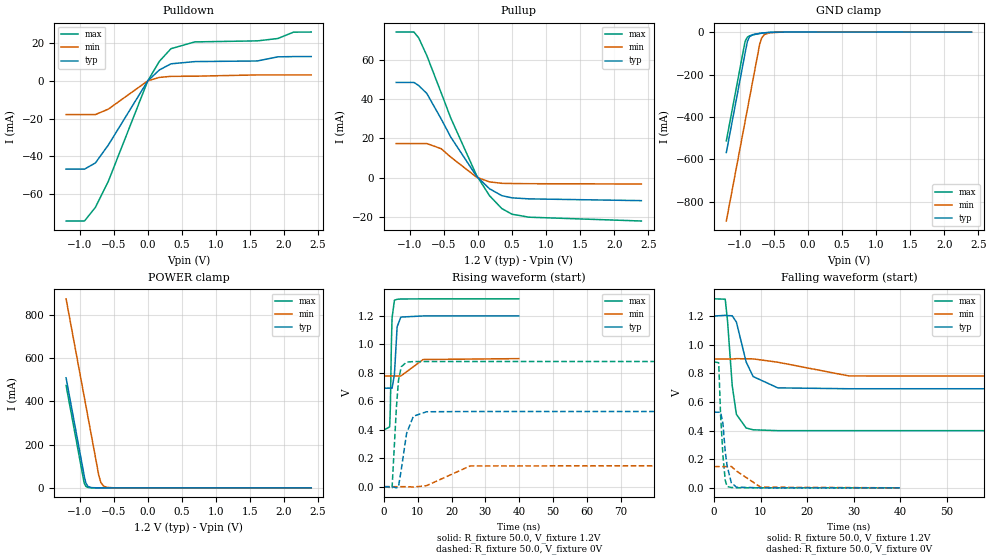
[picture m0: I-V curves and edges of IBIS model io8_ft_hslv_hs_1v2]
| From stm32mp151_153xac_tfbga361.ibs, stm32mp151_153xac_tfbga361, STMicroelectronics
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[Model]   io8_ft_hslv_hs_1v2
Model_type I/O
Polarity   Non-Inverting
Enable   Active-Low
| CAP_THRESHOLD on pad IOFT is "UDTCAPC" :
| Rising=20.00f vddiom   Falling=80.00f vddiom
| C_comp min and max val. don't necessarily correlate with the min and max pvt
| but are the smallest and greatest pad capacitance found.
| var   typ   min   max
C_comp   3.08865pF  3.06550pF  3.10825pF
|C_comp_pullup   1.81640pF  1.58310pF  1.74795pF
|C_comp_pulldown   1.27225pF  1.48240pF  1.36030pF
Vinl = 360.0mV
Vinh = 792.0mV
Vmeas = 600.0mV   | Reference voltage for timing measurements
Cref  = 50.0pF   | Timing specification test load capacitance value
Rref  = 100.0MOhm   | Timing specification test load resistance value
Vref  = 0V   | Timing specification test load voltage
[Model Spec]
| TIME_THRESHOLD on pin ZIV11 is "CMOS" :
| Rising=40.00f vdd   Falling=60.00f vdd
Vinl 463.60000mV 362.60000mV 506.60000mV
Vinh 741.40000mV 545.40000mV 817.40000mV
| variable   typ   min   max
[Temperature Range] 25.0 140.0 -40.0
| variable   typ   min   max
[Voltage Range] 1.2V 900.0mV 1.32V
| variable   typ   min   max
[POWER Clamp Reference] 1.2V 900.0mV 1.32V
| variable   typ   min   max
[GND Clamp Reference] 0V 0V 0V
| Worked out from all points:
|   slope of the pulldown table from 0 to 0.18 V, typ, clamps not added: 30 ohm
|   slope of the pullup table from 0 to 0.18 V, typ, clamps not added: 31.1 ohm
|   GND clamp passes 1 mA (typ) near -0.52 V on its own axis
|   POWER clamp passes 1 mA (typ) near -0.83 V on its own axis
|   rising waveform, R_fixture 50.0, V_fixture 1.2V: 20-80 % time 689ps typ, 1.81ns min, 414ps max; typ from 0.692 V to 1.2 V
|   falling waveform, R_fixture 50.0, V_fixture 1.2V: 20-80 % time 2.79ns typ, 6.92ns min, 1.4ns max; typ from 1.2 V to 0.692 V
|   rising waveform, R_fixture 50.0, V_fixture 0V: 20-80 % time 2.16ns typ, 4.94ns min, 1.21ns max; typ from 0 V to 0.528 V
|   falling waveform, R_fixture 50.0, V_fixture 0V: 20-80 % time 1.12ns typ, 2.39ns min, 840ps max; typ from 0.528 V to 0 V
[POWER Clamp]
-1.2V     508.8mA    874.1mA    473.5mA
-940mV    66.83mA    432.1mA    31.5mA
-930mV    49.83mA    415.1mA    19.15mA
-910mV    22.88mA    381.1mA    7.077mA
-880mV    7.117mA    330.1mA    1.59mA
-830mV    1.017mA    245.1mA    132uA
-720mV    14.05uA    58.12mA    554nA
-690mV    4.373uA    25.03mA    124.7nA
-650mV    922.4nA    8.136mA    17.22nA
-600mV    132.5nA    1.998mA    1.555nA
-490mV    2.736nA    90.9uA     103pA
2.4V      0A         0A         0A
[GND Clamp]
-1.2V     -567.2mA   -889.7mA   -512.2mA
-930mV    -108.2mA   -430.7mA   -53.23mA
-920mV    -91.21mA   -413.7mA   -40.49mA
-890mV    -43.51mA   -362.7mA   -23.59mA
-860mV    -22.57mA   -311.7mA   -17.89mA
-810mV    -12.11mA   -226.7mA   -13.23mA
-710mV    -6.053mA   -57.05mA   -7.064mA
-680mV    -4.908mA   -27.37mA   -5.632mA
-640mV    -3.605mA   -11.51mA   -3.985mA
-560mV    -1.665mA   -3.218mA   -1.61mA
-360mV    -34.72uA   -209.4uA   -9.248uA
2.4V      3.381nA    1.198uA    162.5pA
| variable   typ   min   max
[Pullup Reference] 1.2V 900.0mV 1.32V
| variable   typ   min   max
[Pulldown Reference] 0V 0V 0V
[Pullup]
-1.2V     48.48mA    17.42mA    74.09mA
-940mV    48.48mA    17.42mA    74.09mA
-870mV    46.92mA    17.42mA    71.14mA
-750mV    42.85mA    17.42mA    62.1mA
-540mV    29.95mA    14.82mA    43.25mA
-400mV    20.78mA    10.58mA    30.49mA
-20mV     787.9uA    340.3uA    1.238mA
170mV     -5.53mA    -2.053mA   -9.057mA
350mV     -9.029mA   -2.778mA   -15.58mA
500mV     -10.16mA   -2.879mA   -18.47mA
750mV     -10.68mA   -2.969mA   -19.99mA
2.4V      -11.58mA   -3.134mA   -21.93mA
[Pulldown]
-1.2V     -46.7mA    -17.86mA   -74.13mA
-930mV    -46.7mA    -17.86mA   -74.13mA
-770mV    -43.45mA   -17.86mA   -66.94mA
-580mV    -33.98mA   -14.99mA   -53.18mA
0V        0A         -3pA       0A
170mV     5.742mA    1.792mA    10.3mA
340mV     8.972mA    2.348mA    16.97mA
690mV     10.15mA    2.431mA    20.56mA
1.61V     10.49mA    3.108mA    21.11mA
1.91V     12.66mA    3.108mA    22.36mA
2.14V     12.8mA     3.108mA    25.73mA
2.4V      12.8mA     3.108mA    25.78mA
[Ramp]
dV/dt_r 316.99739mV/2.16461ns 89.08709mV/4.9382ns 527.83784mV/1.2101ns
dV/dt_f 304.66521mV/2.79208ns 73.18473mV/6.92283ns 552.41172mV/1.39788ns
R_load = 50.0
| Removed startup time: 0s 0s 0s  .
| Removed end time: 39.9ns.
[Rising Waveform]
R_fixture   = 50.0
V_fixture   = 1.2V
V_fixture_min = 900.0mV
V_fixture_max = 1.32V
0s        692.2mV    778mV      399.3mV
1.7ns     692.6mV    778.1mV    420.1mV
1.9ns     692.6mV    778.1mV    559.3mV
2.2ns     692.3mV    778.1mV    1.003V
2.4ns     691.3mV    778.1mV    1.187V
3.1ns     788mV      778.1mV    1.31V
3.9ns     1.124V     778.1mV    1.317V
5ns       1.192V     778.1mV    1.319V
11.6ns    1.2V       893.8mV    1.32V
39.9ns    1.2V       900mV      1.32V
| Removed startup time: 0s 0s 0s  .
| Removed end time: 199.9ns.
[Falling Waveform]
R_fixture   = 50.0
V_fixture   = 1.2V
V_fixture_min = 900.0mV
V_fixture_max = 1.32V
0s        1.2V       900mV      1.32V
2.4ns     1.205V     900mV      1.318V
2.9ns     1.203V     900mV      1.164V
3.9ns     1.202V     899.9mV    714.9mV
4.8ns     1.158V     902.4mV    513.4mV
6.9ns     879.3mV    901.1mV    418mV
8.4ns     777.4mV    900.7mV    405.5mV
13.7ns    698.4mV    877.6mV    399.5mV
29ns      692.2mV    781.7mV    399.3mV
199.9ns   692.2mV    778mV      399.3mV
| Removed startup time: 0s 0s 0s  .
| Removed end time: 199.9ns.
[Rising Waveform]
R_fixture   = 50.0
V_fixture   = 0V
V_fixture_min = 0V
V_fixture_max = 0V
0s        -49.46nV   697.7nV    -2.584uV
2.4ns     60.41uV    53.31nV    -8.2mV
3.7ns     -8.111mV   -3.227uV   562.6mV
4.3ns     193.3uV    -1.133uV   745.8mV
5.1ns     115.8mV    1.14uV     842mV
6.7ns     374.3mV    -107.7uV   875.7mV
8.7ns     495.1mV    -2.465mV   879.1mV
12.6ns    526.6mV    7.06mV     879.6mV
25.5ns    528.2mV    145.8mV    879.7mV
199.9ns   528.3mV    148.5mV    879.7mV
| Removed startup time: 0s 0s 0s  .
| Removed end time: 39.9ns.
[Falling Waveform]
R_fixture   = 50.0
V_fixture   = 0V
V_fixture_min = 0V
V_fixture_max = 0V
0s        528.3mV    148.5mV    879.7mV
1ns       528.4mV    148.5mV    873.7mV
1.4ns     529.1mV    148.5mV    508mV
1.9ns     450.6mV    148.5mV    228.6mV
2.4ns     253.3mV    148.5mV    53.1mV
2.8ns     153.9mV    148.5mV    9.578mV
3.7ns     36.42mV    149.8mV    2.479mV
4.8ns     4.812mV    117.7mV    920.1uV
10ns      258.6uV    4.938mV    32.97uV
39.9ns    34.97nV    3.183uV    29.06nV
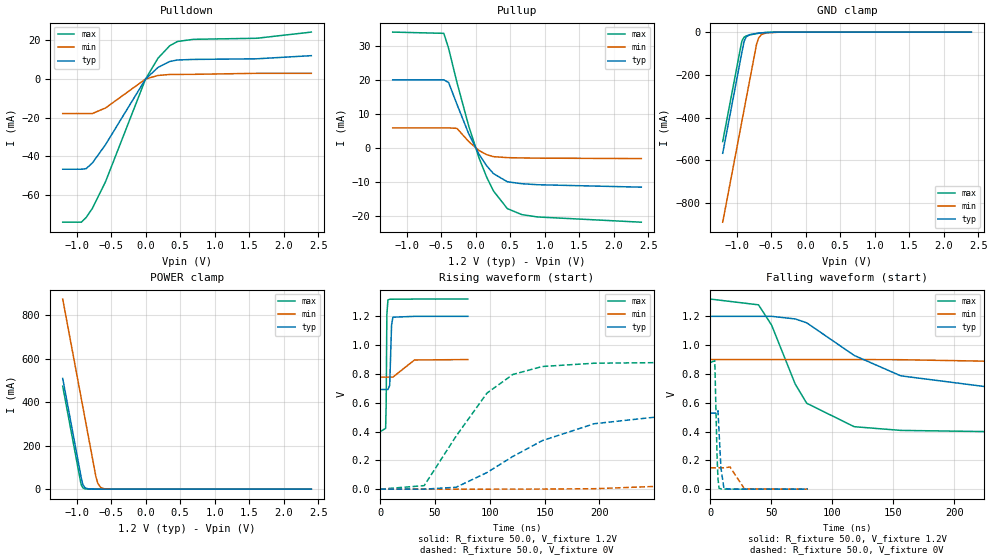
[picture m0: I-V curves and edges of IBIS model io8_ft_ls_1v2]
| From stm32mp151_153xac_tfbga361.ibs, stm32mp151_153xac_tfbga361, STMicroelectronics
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[Model]   io8_ft_ls_1v2
Model_type I/O
Polarity   Non-Inverting
Enable   Active-Low
| CAP_THRESHOLD on pad IOFT is "UDTCAPC" :
| Rising=20.00f vddiom   Falling=80.00f vddiom
| C_comp min and max val. don't necessarily correlate with the min and max pvt
| but are the smallest and greatest pad capacitance found.
| var   typ   min   max
C_comp   3.10955pF  3.08200pF  3.12755pF
|C_comp_pullup   1.83575pF  1.59880pF  1.76540pF
|C_comp_pulldown   1.27380pF  1.48320pF  1.36215pF
Vinl = 360.0mV
Vinh = 792.0mV
Vmeas = 600.0mV   | Reference voltage for timing measurements
Cref  = 50.0pF   | Timing specification test load capacitance value
Rref  = 100.0MOhm   | Timing specification test load resistance value
Vref  = 0V   | Timing specification test load voltage
[Model Spec]
| TIME_THRESHOLD on pin ZIV11 is "CMOS" :
| Rising=40.00f vdd   Falling=60.00f vdd
Vinl 463.60000mV 362.60000mV 506.60000mV
Vinh 741.40000mV 545.40000mV 817.40000mV
| variable   typ   min   max
[Temperature Range] 25.0 140.0 -40.0
| variable   typ   min   max
[Voltage Range] 1.2V 900.0mV 1.32V
| variable   typ   min   max
[POWER Clamp Reference] 1.2V 900.0mV 1.32V
| variable   typ   min   max
[GND Clamp Reference] 0V 0V 0V
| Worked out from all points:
|   slope of the pulldown table from 0 to 0.18 V, typ, clamps not added: 30 ohm
|   slope of the pullup table from 0 to 0.18 V, typ, clamps not added: 31.1 ohm
|   GND clamp passes 1 mA (typ) near -0.52 V on its own axis
|   POWER clamp passes 1 mA (typ) near -0.83 V on its own axis
|   rising waveform, R_fixture 50.0, V_fixture 1.2V: 20-80 % time 987ps typ, 2.96ns min, 508ps max; typ from 0.692 V to 1.2 V
|   falling waveform, R_fixture 50.0, V_fixture 1.2V: 20-80 % time 62.7ns typ, 177ns min, 29.8ns max; typ from 1.2 V to 0.692 V
|   rising waveform, R_fixture 50.0, V_fixture 0V: 20-80 % time 82.5ns typ, 195ns min, 47.7ns max; typ from 0 V to 0.528 V
|   falling waveform, R_fixture 50.0, V_fixture 0V: 20-80 % time 2.14ns typ, 4.88ns min, 1.52ns max; typ from 0.528 V to 0 V
[POWER Clamp]
-1.2V     508.8mA    874.1mA    473.5mA
-940mV    66.83mA    432.1mA    31.5mA
-930mV    49.83mA    415.1mA    19.15mA
-910mV    22.88mA    381.1mA    7.077mA
-880mV    7.117mA    330.1mA    1.59mA
-830mV    1.017mA    245.1mA    132uA
-720mV    14.05uA    58.12mA    554nA
-690mV    4.373uA    25.03mA    124.7nA
-650mV    922.4nA    8.136mA    17.22nA
-600mV    132.5nA    1.998mA    1.555nA
-490mV    2.763nA    90.9uA     103.5pA
2.4V      0A         0A         0A
[GND Clamp]
-1.2V     -567.2mA   -889.7mA   -512.2mA
-930mV    -108.2mA   -430.7mA   -53.23mA
-920mV    -91.21mA   -413.7mA   -40.49mA
-890mV    -43.51mA   -362.7mA   -23.59mA
-860mV    -22.57mA   -311.7mA   -17.89mA
-810mV    -12.11mA   -226.7mA   -13.23mA
-710mV    -6.053mA   -57.05mA   -7.064mA
-680mV    -4.908mA   -27.37mA   -5.632mA
-640mV    -3.605mA   -11.51mA   -3.985mA
-560mV    -1.665mA   -3.218mA   -1.61mA
-360mV    -34.72uA   -209.4uA   -9.248uA
2.4V      3.381nA    1.198uA    162.5pA
| variable   typ   min   max
[Pullup Reference] 1.2V 900.0mV 1.32V
| variable   typ   min   max
[Pulldown Reference] 0V 0V 0V
[Pullup]
-1.2V     20.14mA    5.941mA    34.24mA
-460mV    20.14mA    5.941mA    33.87mA
-390mV    19.31mA    5.941mA    29.39mA
-270mV    12.92mA    5.787mA    19.38mA
-100mV    4.22mA     1.911mA    6.527mA
50mV      -1.845mA   -758.1uA   -2.941mA
160mV     -5.263mA   -1.972mA   -8.6mA
260mV     -7.588mA   -2.569mA   -12.73mA
460mV     -9.985mA   -2.858mA   -17.92mA
670mV     -10.56mA   -2.944mA   -19.69mA
900mV     -10.86mA   -3.007mA   -20.39mA
2.4V      -11.58mA   -3.134mA   -21.93mA
[Pulldown]
-1.2V     -46.7mA    -17.86mA   -74.13mA
-930mV    -46.7mA    -17.86mA   -74.13mA
-860mV    -46.38mA   -17.86mA   -71.67mA
-770mV    -43.45mA   -17.86mA   -66.94mA
-580mV    -33.98mA   -14.99mA   -53.18mA
0V        0A         0A         0A
180mV     6.001mA    1.854mA    10.79mA
350mV     9.086mA    2.357mA    17.24mA
460mV     9.857mA    2.399mA    19.42mA
690mV     10.15mA    2.431mA    20.56mA
1.61V     10.48mA    2.965mA    21.11mA
2.4V      12.11mA    2.965mA    24.31mA
[Ramp]
dV/dt_r 316.97841mV/82.49598ns 88.45552mV/195.47658ns 527.82343mV/47.69496ns
dV/dt_f 304.65738mV/62.70339ns 72.73727mV/175.08762ns 552.41102mV/29.81872ns
R_load = 50.0
| Removed startup time: 0s 0s 0s  .
| Removed end time: 79.9ns.
[Rising Waveform]
R_fixture   = 50.0
V_fixture   = 1.2V
V_fixture_min = 900.0mV
V_fixture_max = 1.32V
0s        692.2mV    778mV      399.3mV
4.9ns     692.2mV    778mV      422.3mV
5.4ns     692.2mV    778mV      597.9mV
6ns       692.3mV    778mV      1.212V
7ns       691.6mV    778mV      1.314V
8.6ns     720.2mV    778mV      1.319V
10.3ns    1.14V      778mV      1.319V
11.5ns    1.194V     778mV      1.319V
31.2ns    1.2V       896.9mV    1.32V
79.9ns    1.2V       899.9mV    1.32V
| Removed startup time: 0s 0s 0s  .
| Removed end time: 799.9ns.
[Falling Waveform]
R_fixture   = 50.0
V_fixture   = 1.2V
V_fixture_min = 900.0mV
V_fixture_max = 1.32V
0s        1.2V       900mV      1.32V
39.5ns    1.2V       900.1mV    1.28V
50.3ns    1.2V       900mV      1.138V
69.6ns    1.182V     900mV      729.4mV
79ns      1.155V     900mV      596.4mV
117.9ns   928.6mV    900mV      433.8mV
156ns     787mV      898.9mV    408.1mV
224.4ns   713mV      888.9mV    400mV
444.4ns   692.4mV    800.4mV    399.3mV
799.9ns   692.2mV    778.8mV    399.3mV
| Removed startup time: 0s 0s 0s  .
| Removed end time: 799.9ns.
[Rising Waveform]
R_fixture   = 50.0
V_fixture   = 0V
V_fixture_min = 0V
V_fixture_max = 0V
0s        50.56nV    1.017uV    137.1nV
40.1ns    -72.19uV   -26.3uV    24.69mV
69.3ns    13.35mV    -3.105uV   369.2mV
97.4ns    115.4mV    34.09uV    667.1mV
121ns     227.2mV    177.3uV    796.4mV
147.9ns   337.1mV    642.8uV    851.7mV
195.3ns   454.4mV    3.028mV    874.5mV
265.7ns   512.1mV    23.15mV    879.4mV
490ns     528.1mV    122.7mV    879.7mV
799.9ns   528.3mV    147.4mV    879.7mV
| Removed startup time: 0s 0s 0s  .
| Removed end time: 79.9ns.
[Falling Waveform]
R_fixture   = 50.0
V_fixture   = 0V
V_fixture_min = 0V
V_fixture_max = 0V
0s        528.3mV    148.5mV    879.7mV
3.7ns     528.3mV    148.5mV    890.9mV
5.5ns     529.1mV    148.5mV    245.2mV
6.3ns     544.5mV    148.5mV    72.91mV
7.2ns     396.6mV    148.5mV    6.735mV
8.7ns     149.3mV    148.5mV    1.774mV
11.2ns    5.194mV    148.5mV    520.6uV
16.2ns    350.8uV    153.7mV    289.9uV
28ns      125.5uV    1.631mV    273.3uV
79.9ns    139.6uV    28.79uV    55.94uV
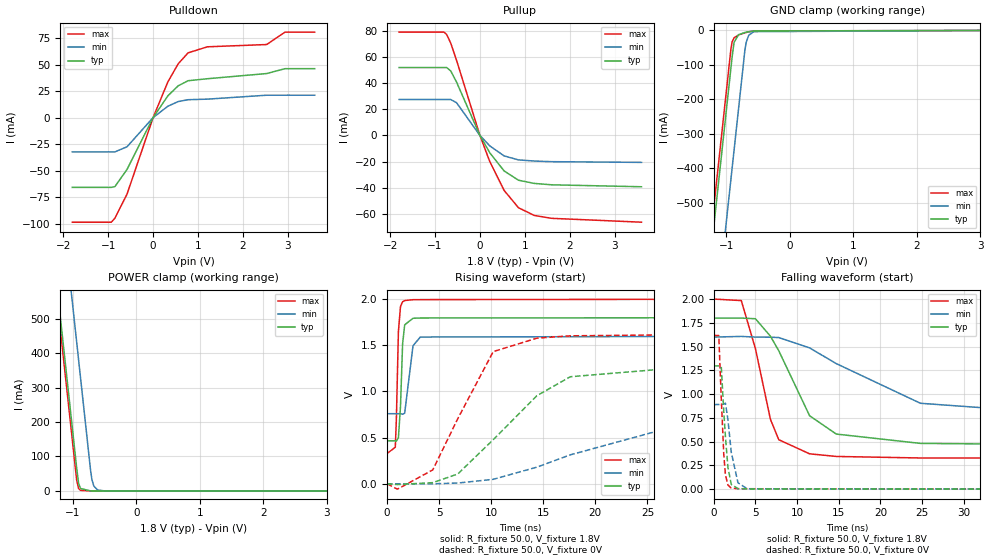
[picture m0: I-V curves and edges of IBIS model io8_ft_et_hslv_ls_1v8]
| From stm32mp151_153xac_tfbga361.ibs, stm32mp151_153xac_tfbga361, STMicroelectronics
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[Model]   io8_ft_et_hslv_ls_1v8
Model_type I/O
Polarity   Non-Inverting
Enable   Active-Low
| CAP_THRESHOLD on pad IOFT is "UDTCAPC" :
| Rising=20.00f vddiom   Falling=80.00f vddiom
| C_comp min and max val. don't necessarily correlate with the min and max pvt
| but are the smallest and greatest pad capacitance found.
| var   typ   min   max
C_comp   3.43098pF  3.42356pF  3.49920pF
|C_comp_pullup   1.96775pF  2.05990pF  1.91900pF
|C_comp_pulldown   1.46323pF  1.36366pF  1.58020pF
Vinl = 640.0mV
Vinh = 1.2V
Vmeas = 900.0mV   | Reference voltage for timing measurements
Cref  = 50.0pF   | Timing specification test load capacitance value
Rref  = 100.0MOhm   | Timing specification test load resistance value
Vref  = 0V   | Timing specification test load voltage
[Model Spec]
| TIME_THRESHOLD on pin ZIV11 is "CMOS" :
| Rising=40.00f vdd   Falling=60.00f vdd
Vinl 738.60000mV 665.60000mV 824.60000mV
Vinh 1.04640V 924.40000mV 1.13940V
| variable   typ   min   max
[Temperature Range] 25.0 140.0 -40.0
| variable   typ   min   max
[Voltage Range] 1.8V 1.6V 2.0V
| variable   typ   min   max
[POWER Clamp Reference] 1.8V 1.6V 2.0V
| variable   typ   min   max
[GND Clamp Reference] 0V 0V 0V
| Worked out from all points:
|   slope of the pulldown table from 0 to 0.27 V, typ, clamps not added: 16 ohm
|   slope of the pullup table from 0 to 0.27 V, typ, clamps not added: 17 ohm
|   GND clamp passes 1 mA (typ) near -0.52 V on its own axis
|   POWER clamp passes 1 mA (typ) near -0.83 V on its own axis
|   rising waveform, R_fixture 50.0, V_fixture 1.8V: 20-80 % time 258ps typ, 399ps min, 218ps max; typ from 0.466 V to 1.8 V
|   falling waveform, R_fixture 50.0, V_fixture 1.8V: 20-80 % time 4.53ns typ, 10.9ns min, 2.52ns max; typ from 1.8 V to 0.466 V
|   rising waveform, R_fixture 50.0, V_fixture 0V: 20-80 % time 7ns typ, 15.5ns min, 3.89ns max; typ from 0 V to 1.3 V
|   falling waveform, R_fixture 50.0, V_fixture 0V: 20-80 % time 589ps typ, 785ps min, 467ps max; typ from 1.3 V to 0 V
[POWER Clamp]
-1.8V     1.529A     1.894A     1.494A
-940mV    66.83mA    432.1mA    31.5mA
-910mV    22.88mA    381.1mA    7.077mA
-880mV    7.117mA    330.1mA    1.59mA
-720mV    14.05uA    58.12mA    554nA
-700mV    6.453uA    33.14mA    205nA
-670mV    2.008uA    14.27mA    46.29nA
-610mV    195.5nA    2.645mA    2.508nA
-500mV    3.96nA     120.4uA    139.7pA
3.6V      0A         0A         0A
[GND Clamp]
-1.8V     -1.588A    -1.91A     -1.533A
-1.26V    -670.3mA   -992.4mA   -614.9mA
-1.2V     -568.3mA   -890.4mA   -512.9mA
-930mV    -109.3mA   -431.4mA   -53.86mA
-910mV    -75.33mA   -397.4mA   -32.91mA
-880mV    -34.88mA   -346.4mA   -21.56mA
-810mV    -12.56mA   -227.4mA   -13.55mA
-710mV    -6.275mA   -57.63mA   -7.234mA
-690mV    -5.461mA   -35.21mA   -6.234mA
-650mV    -4.039mA   -14.43mA   -4.463mA
-570mV    -1.908mA   -3.832mA   -1.869mA
3.6V      5.084nA    1.599uA    245.6pA
| variable   typ   min   max
[Pullup Reference] 1.8V 1.6V 2.0V
| variable   typ   min   max
[Pulldown Reference] 0V 0V 0V
[Pullup]
-1.8V     51.8mA     27.39mA    78.89mA
-800mV    51.8mA     27.39mA    78.89mA
-740mV    51.8mA     27.39mA    77.04mA
-650mV    49.26mA    27.39mA    70.49mA
-520mV    40.7mA     24.96mA    57.36mA
0V        7.41pA     1.331nA    4.294pA
220mV     -13.28mA   -8.01mA    -19.99mA
540mV     -27.17mA   -15.69mA   -42.05mA
860mV     -34.25mA   -18.73mA   -55.26mA
1.21V     -36.68mA   -19.6mA    -61.13mA
1.6V      -37.75mA   -20.08mA   -63.35mA
3.6V      -39.24mA   -20.62mA   -66.3mA
[Pulldown]
-1.8V     -65.8mA    -32.31mA   -98.64mA
-930mV    -65.8mA    -32.31mA   -98.64mA
-850mV    -65.04mA   -32.31mA   -94.81mA
-580mV    -48.83mA   -27.49mA   -72.14mA
0V        0A         -3pA       0A
330mV     20.59mA    10.79mA    33.74mA
560mV     30.02mA    15.15mA    50.81mA
780mV     34.81mA    16.9mA     61.1mA
1.21V     36.69mA    17.44mA    66.81mA
2.53V     41.58mA    21.14mA    68.95mA
2.94V     46.18mA    21.14mA    80.69mA
3.6V      46.18mA    21.14mA    80.69mA
[Ramp]
dV/dt_r 777.92781mV/6.99993ns 534.16918mV/15.51711ns 970.1271mV/3.88692ns
dV/dt_f 800.5972mV/4.5251ns 504.69998mV/10.92983ns 1.00395V/2.5137ns
R_load = 50.0
| Removed startup time: 0s 0s 0s  .
| Removed end time: 49.9ns.
[Rising Waveform]
R_fixture   = 50.0
V_fixture   = 1.8V
V_fixture_min = 1.6V
V_fixture_max = 2.0V
0s        465.7mV    758.8mV    326.7mV
800ps     465.2mV    758.9mV    395.8mV
900ps     461mV      758.9mV    690.1mV
1.1ns     498.4mV    758.8mV    1.65V
1.3ns     838.9mV    759mV      1.92V
1.5ns     1.512V     753.4mV    1.971V
1.7ns     1.721V     764mV      1.984V
2.5ns     1.792V     1.494V     1.993V
3.2ns     1.795V     1.589V     1.994V
49.9ns    1.8V       1.6V       2V
| Removed startup time: 0s 0s 0s  .
| Removed end time: 279.9ns.
[Falling Waveform]
R_fixture   = 50.0
V_fixture   = 1.8V
V_fixture_min = 1.6V
V_fixture_max = 2.0V
0s        1.8V       1.6V       2V
3.3ns     1.8V       1.607V     1.984V
5ns       1.793V     1.6V       1.478V
6.8ns     1.609V     1.599V     734.3mV
7.8ns     1.456V     1.595V     520.3mV
11.5ns    772.4mV    1.486V     371.8mV
14.7ns    579.7mV    1.321V     344.2mV
24.8ns    481.5mV    903.6mV    328.1mV
45.4ns    466.2mV    773.9mV    326.7mV
279.9ns   465.7mV    758.8mV    326.7mV
| Removed startup time: 0s 0s 0s  .
| Removed end time: 279.9ns.
[Rising Waveform]
R_fixture   = 50.0
V_fixture   = 0V
V_fixture_min = 0V
V_fixture_max = 0V
0s        169.1nV    -242nV     -4.867uV
1ns       -8.395mV   -89.61uV   -58.18mV
4.4ns     12.46mV    -261.8uV   150.9mV
6.8ns     106.3mV    8.15mV     705.5mV
10.2ns    477.5mV    48.4mV     1.431V
14.4ns    954.3mV    180.5mV    1.577V
17.6ns    1.159V     313.4mV    1.602V
31.6ns    1.289V     744.2mV    1.617V
50.9ns    1.296V     873.8mV    1.617V
279.9ns   1.297V     890.3mV    1.617V
| Removed startup time: 0s 0s 0s  .
| Removed end time: 49.9ns.
[Falling Waveform]
R_fixture   = 50.0
V_fixture   = 0V
V_fixture_min = 0V
V_fixture_max = 0V
0s        1.297V     890.3mV    1.617V
600ps     1.296V     890.4mV    1.616V
900ps     1.292V     890.6mV    952.5mV
1.2ns     810.4mV    895mV      366.1mV
1.4ns     551.5mV    904.7mV    150.7mV
1.7ns     229.1mV    729.5mV    43.25mV
2.1ns     50.05mV    388.1mV    11.1mV
2.9ns     5.096mV    67.91mV    4.999mV
4ns       2.785mV    4.354mV    4.542mV
49.9ns    4.402uV    16.85uV    7.556uV
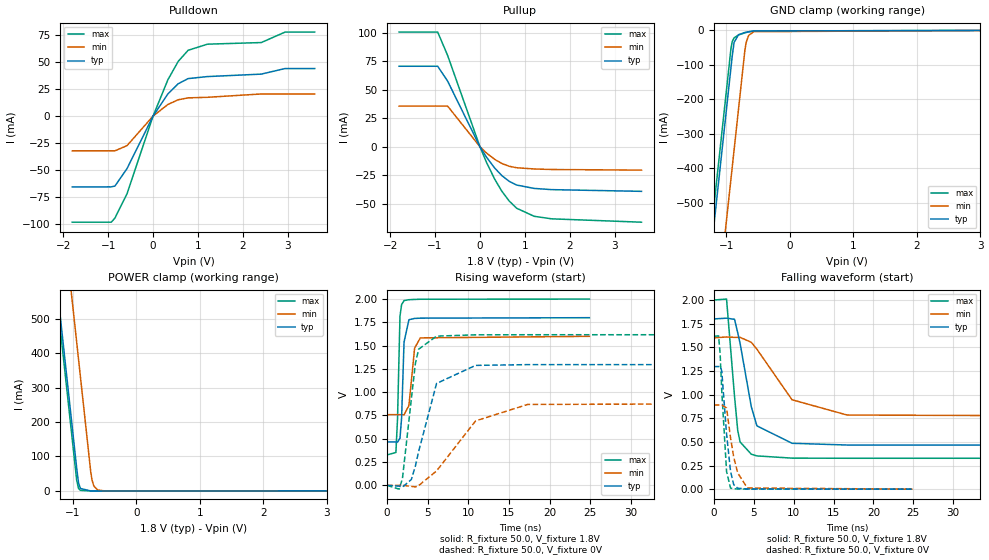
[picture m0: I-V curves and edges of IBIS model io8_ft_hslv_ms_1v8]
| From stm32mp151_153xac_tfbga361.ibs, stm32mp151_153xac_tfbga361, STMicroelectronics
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[Model]   io8_ft_hslv_ms_1v8
Model_type I/O
Polarity   Non-Inverting
Enable   Active-Low
| CAP_THRESHOLD on pad IOFT is "UDTCAPC" :
| Rising=20.00f vddiom   Falling=80.00f vddiom
| C_comp min and max val. don't necessarily correlate with the min and max pvt
| but are the smallest and greatest pad capacitance found.
| var   typ   min   max
C_comp   3.40998pF  3.40231pF  3.47825pF
|C_comp_pullup   1.96225pF  2.05415pF  1.91340pF
|C_comp_pulldown   1.44773pF  1.34816pF  1.56485pF
Vinl = 640.0mV
Vinh = 1.2V
Vmeas = 900.0mV   | Reference voltage for timing measurements
Cref  = 50.0pF   | Timing specification test load capacitance value
Rref  = 100.0MOhm   | Timing specification test load resistance value
Vref  = 0V   | Timing specification test load voltage
[Model Spec]
| TIME_THRESHOLD on pin ZIV11 is "CMOS" :
| Rising=40.00f vdd   Falling=60.00f vdd
Vinl 738.60000mV 665.60000mV 824.60000mV
Vinh 1.04640V 924.40000mV 1.13940V
| variable   typ   min   max
[Temperature Range] 25.0 140.0 -40.0
| variable   typ   min   max
[Voltage Range] 1.8V 1.6V 2.0V
| variable   typ   min   max
[POWER Clamp Reference] 1.8V 1.6V 2.0V
| variable   typ   min   max
[GND Clamp Reference] 0V 0V 0V
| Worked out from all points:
|   slope of the pulldown table from 0 to 0.27 V, typ, clamps not added: 16 ohm
|   slope of the pullup table from 0 to 0.27 V, typ, clamps not added: 17 ohm
|   GND clamp passes 1 mA (typ) near -0.52 V on its own axis
|   POWER clamp passes 1 mA (typ) near -0.83 V on its own axis
|   rising waveform, R_fixture 50.0, V_fixture 1.8V: 20-80 % time 294ps typ, 527ps min, 244ps max; typ from 0.466 V to 1.8 V
|   falling waveform, R_fixture 50.0, V_fixture 1.8V: 20-80 % time 1.79ns typ, 4.31ns min, 937ps max; typ from 1.8 V to 0.466 V
|   rising waveform, R_fixture 50.0, V_fixture 0V: 20-80 % time 2.2ns typ, 4.94ns min, 1.16ns max; typ from 0 V to 1.3 V
|   falling waveform, R_fixture 50.0, V_fixture 0V: 20-80 % time 807ps typ, 1.14ns min, 602ps max; typ from 1.3 V to 0 V
[POWER Clamp]
-1.8V     1.529A     1.894A     1.494A
-940mV    66.83mA    432.1mA    31.5mA
-910mV    22.88mA    381.1mA    7.077mA
-880mV    7.117mA    330.1mA    1.59mA
-720mV    14.05uA    58.12mA    554nA
-700mV    6.453uA    33.14mA    205nA
-670mV    2.008uA    14.27mA    46.28nA
-610mV    195.3nA    2.645mA    2.496nA
-500mV    3.825nA    120.4uA    129.9pA
3.6V      0A         0A         0A
[GND Clamp]
-1.8V     -1.588A    -1.91A     -1.533A
-1.26V    -670.3mA   -992.4mA   -614.9mA
-1.2V     -568.3mA   -890.4mA   -512.9mA
-930mV    -109.3mA   -431.4mA   -53.86mA
-910mV    -75.33mA   -397.4mA   -32.91mA
-880mV    -34.88mA   -346.4mA   -21.56mA
-810mV    -12.56mA   -227.4mA   -13.55mA
-710mV    -6.275mA   -57.63mA   -7.234mA
-690mV    -5.461mA   -35.21mA   -6.234mA
-650mV    -4.039mA   -14.43mA   -4.463mA
-570mV    -1.908mA   -3.832mA   -1.869mA
3.6V      5.036nA    1.588uA    245.5pA
| variable   typ   min   max
[Pullup Reference] 1.8V 1.6V 2.0V
| variable   typ   min   max
[Pulldown Reference] 0V 0V 0V
[Pullup]
-1.8V     70.45mA    35.56mA    100.4mA
-940mV    70.45mA    35.56mA    100.4mA
-720mV    57.51mA    35.56mA    80.06mA
0V        7.41pA     1.331nA    4.294pA
150mV     -9.369mA   -5.694mA   -14.02mA
330mV     -18.8mA    -11.18mA   -28.55mA
490mV     -25.43mA   -14.8mA    -39.16mA
650mV     -30.35mA   -17.2mA    -47.56mA
820mV     -33.69mA   -18.53mA   -54.05mA
1.21V     -36.65mA   -19.59mA   -61.09mA
1.6V      -37.71mA   -20.06mA   -63.31mA
3.6V      -39.21mA   -20.61mA   -66.25mA
[Pulldown]
-1.8V     -65.8mA    -32.31mA   -98.64mA
-930mV    -65.8mA    -32.31mA   -98.64mA
-850mV    -65.04mA   -32.31mA   -94.81mA
-580mV    -48.83mA   -27.49mA   -72.14mA
0V        0A         -2pA       0A
330mV     20.59mA    10.79mA    33.74mA
560mV     30.02mA    15.15mA    50.81mA
780mV     34.81mA    16.9mA     61.1mA
1.21V     36.69mA    17.44mA    66.81mA
2.41V     38.98mA    20.52mA    68.31mA
2.94V     44.17mA    20.52mA    78.04mA
3.6V      44.17mA    20.52mA    78.04mA
[Ramp]
dV/dt_r 777.74841mV/2.1949ns 533.90848mV/4.93647ns 970.0132mV/1.15778ns
dV/dt_f 800.59689mV/1.78442ns 504.71812mV/4.3089ns 1.00395V/934.04661ps
R_load = 50.0
| Removed startup time: 0s 0s 0s  .
| Removed end time: 24.9ns.
[Rising Waveform]
R_fixture   = 50.0
V_fixture   = 1.8V
V_fixture_min = 1.6V
V_fixture_max = 2.0V
0s        465.7mV    758.8mV    326.7mV
1.1ns     465.7mV    758.9mV    352.9mV
1.3ns     463.6mV    759mV      716.8mV
1.6ns     506.9mV    759mV      1.816V
1.8ns     723mV      758.9mV    1.94V
2.1ns     1.538V     756.8mV    1.984V
2.7ns     1.778V     857.1mV    1.993V
3.4ns     1.792V     1.473V     1.996V
4.1ns     1.795V     1.583V     1.998V
24.9ns    1.8V       1.6V       2V
| Removed startup time: 0s 0s 0s  .
| Removed end time: 99.9ns.
[Falling Waveform]
R_fixture   = 50.0
V_fixture   = 1.8V
V_fixture_min = 1.6V
V_fixture_max = 2.0V
0s        1.8V       1.6V       2V
1.6ns     1.808V     1.609V     2.01V
2.6ns     1.796V     1.605V     979.9mV
3ns       1.654V     1.605V     621mV
3.3ns     1.54V      1.605V     498.5mV
4.7ns     871.3mV    1.553V     369.6mV
5.4ns     669.6mV    1.48V      351.7mV
9.8ns     485.1mV    945.2mV    328.1mV
16.7ns    466.7mV    783.9mV    326.8mV
99.9ns    465.7mV    758.8mV    326.7mV
| Removed startup time: 0s 0s 0s  .
| Removed end time: 99.9ns.
[Rising Waveform]
R_fixture   = 50.0
V_fixture   = 0V
V_fixture_min = 0V
V_fixture_max = 0V
0s        59.82nV    175nV      -3.129uV
1.5ns     -8.734mV   2.256uV    -41.08mV
1.9ns     -18.83mV   174.9uV    70.97mV
3ns       62.71mV    -11.33mV   928.5mV
3.5ns     208.6mV    -16.5mV    1.311V
3.9ns     364.4mV    -2.391mV   1.462V
6.1ns     1.094V     154.6mV    1.602V
10.9ns    1.288V     691.8mV    1.616V
17.3ns    1.296V     868.5mV    1.617V
99.9ns    1.296V     889.8mV    1.617V
| Removed startup time: 0s 0s 0s  .
| Removed end time: 24.9ns.
[Falling Waveform]
R_fixture   = 50.0
V_fixture   = 0V
V_fixture_min = 0V
V_fixture_max = 0V
0s        1.296V     889.9mV    1.617V
600ps     1.296V     889.9mV    1.621V
800ps     1.299V     890mV      1.428V
1ns       1.249V     889.9mV    1.04V
1.6ns     583.9mV    858.5mV    187.6mV
2.1ns     188.4mV    543.9mV    11.6mV
2.5ns     47.49mV    337.4mV    4.041mV
3ns       9.873mV    170.6mV    2.288mV
4.2ns     2.317mV    12.57mV    1.119mV
24.9ns    796nV      14.42uV    -806.5nV
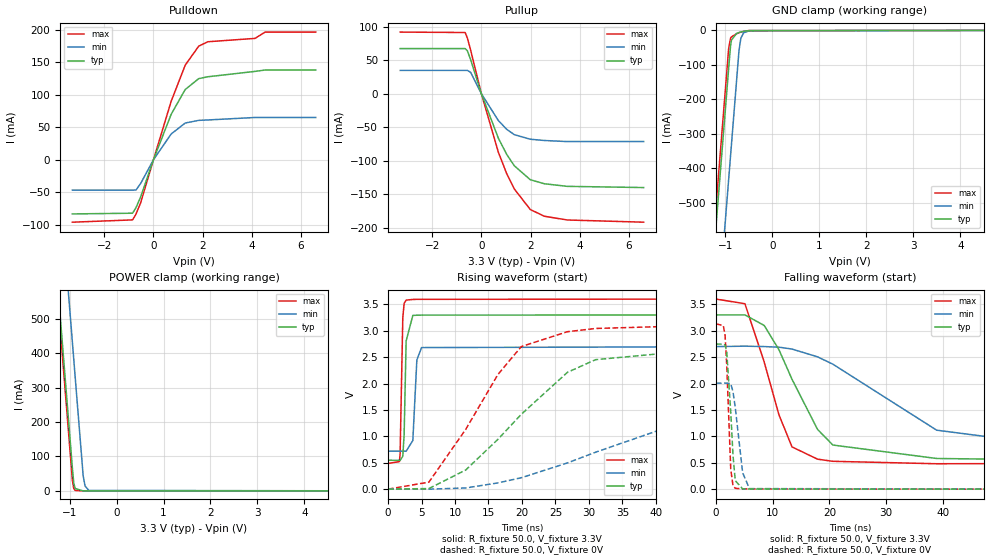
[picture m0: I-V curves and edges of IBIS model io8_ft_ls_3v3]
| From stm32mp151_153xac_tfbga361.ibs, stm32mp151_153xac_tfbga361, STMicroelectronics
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[Model]   io8_ft_ls_3v3
Model_type I/O
Polarity   Non-Inverting
Enable   Active-Low
| CAP_THRESHOLD on pad IOFT is "UDTCAPC" :
| Rising=20.00f vddiom   Falling=80.00f vddiom
| C_comp min and max val. don't necessarily correlate with the min and max pvt
| but are the smallest and greatest pad capacitance found.
| var   typ   min   max
C_comp   3.69202pF  3.65664pF  3.71215pF
|C_comp_pullup   2.23630pF  2.30075pF  2.13670pF
|C_comp_pulldown   1.45572pF  1.35589pF  1.57545pF
Vinl = 1.08V
Vinh = 2.16V
Vmeas = 1.65V   | Reference voltage for timing measurements
Cref  = 50.0pF   | Timing specification test load capacitance value
Rref  = 100.0MOhm   | Timing specification test load resistance value
Vref  = 0V   | Timing specification test load voltage
[Model Spec]
| TIME_THRESHOLD on pin ZIV11 is "CMOS" :
| Rising=40.00f vdd   Falling=60.00f vdd
Vinl 1.36060V 1.12960V 1.47360V
Vinh 1.71540V 1.45040V 1.82940V
| variable   typ   min   max
[Temperature Range] 25.0 140.0 -40.0
| variable   typ   min   max
[Voltage Range] 3.3V 2.7V 3.6V
| variable   typ   min   max
[POWER Clamp Reference] 3.3V 2.7V 3.6V
| variable   typ   min   max
[GND Clamp Reference] 0V 0V 0V
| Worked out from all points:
|   slope of the pulldown table from 0 to 0.495 V, typ, clamps not added: 9.86 ohm
|   slope of the pullup table from 0 to 0.495 V, typ, clamps not added: 9.93 ohm
|   GND clamp passes 1 mA (typ) near -0.52 V on its own axis
|   POWER clamp passes 1 mA (typ) near -0.83 V on its own axis
|   rising waveform, R_fixture 50.0, V_fixture 3.3V: 20-80 % time 278ps typ, 397ps min, 264ps max; typ from 0.547 V to 3.3 V
|   falling waveform, R_fixture 50.0, V_fixture 3.3V: 20-80 % time 7.51ns typ, 17.3ns min, 4.93ns max; typ from 3.3 V to 0.547 V
|   rising waveform, R_fixture 50.0, V_fixture 0V: 20-80 % time 13.3ns typ, 26.4ns min, 9.1ns max; typ from 0 V to 2.75 V
|   falling waveform, R_fixture 50.0, V_fixture 0V: 20-80 % time 815ps typ, 1.23ns min, 646ps max; typ from 2.75 V to 0 V
[POWER Clamp]
-3.3V     4.079A     4.444A     4.043A
-1.46V    950.8mA    1.316A     915.5mA
-1.28V    644.8mA    1.01A      609.5mA
-1.1V     338.8mA    704.1mA    303.5mA
-1.09V    321.8mA    687.1mA    286.5mA
-940mV    66.83mA    432.1mA    31.5mA
-910mV    22.88mA    381.1mA    7.077mA
-880mV    7.117mA    330.1mA    1.59mA
-710mV    9.523uA    43.89mA    337nA
-670mV    2.009uA    14.27mA    46.35nA
-590mV    90.76nA    1.508mA    1.088nA
6.6V      0A         0A         0A
[GND Clamp]
-3.3V     -4.139A    -4.461A    -4.081A
-1.26V    -670.8mA   -992.8mA   -613.3mA
-1.1V     -398.8mA   -720.8mA   -341.3mA
-930mV    -109.8mA   -431.8mA   -52.32mA
-890mV    -44.91mA   -363.8mA   -23.04mA
-870mV    -28.43mA   -329.8mA   -18.86mA
-760mV    -8.879mA   -142.8mA   -9.749mA
-710mV    -6.383mA   -58.04mA   -7.036mA
-670mV    -4.798mA   -22.41mA   -5.193mA
-610mV    -2.902mA   -7.057mA   -2.962mA
-500mV    -778.4uA   -1.643mA   -611.3uA
6.6V      9.179nA    3.066uA    465pA
| variable   typ   min   max
[Pullup Reference] 3.3V 2.7V 3.6V
| variable   typ   min   max
[Pulldown Reference] 0V 0V 0V
[Pullup]
-3.3V     67.38mA    34.8mA     92mA
-660mV    67.38mA    34.8mA     91.37mA
-570mV    64.02mA    34.8mA     83.16mA
-440mV    51.17mA    32.01mA    65.5mA
0V        11.24pA    1.438nA    7.78pA
690mV     -66.37mA   -40.04mA   -87.36mA
1.03V     -90.57mA   -53.18mA   -119.3mA
1.34V     -107.6mA   -61.16mA   -142.2mA
1.99V     -128.4mA   -67.95mA   -172.9mA
2.56V     -134.4mA   -69.84mA   -182.9mA
3.49V     -138.3mA   -71.44mA   -188.5mA
6.6V      -140.1mA   -71.44mA   -191.8mA
[Pulldown]
-3.3V     -83.56mA   -46.9mA    -96.31mA
-850mV    -82.46mA   -46.9mA    -92.78mA
-710mV    -73.83mA   -46.68mA   -83.86mA
-520mV    -57.22mA   -36.51mA   -66.23mA
0V        30fA       -1pA       200fA
720mV     70.07mA    39.69mA    90.11mA
1.29V     108.2mA    56.55mA    145.7mA
1.84V     125mA      60.7mA     175.1mA
2.21V     127.9mA    61.3mA     181.9mA
4.13V     136.2mA    65.14mA    187.1mA
4.54V     138.3mA    65.14mA    196.8mA
6.6V      138.3mA    65.14mA    196.8mA
[Ramp]
dV/dt_r 1.64844V/13.34545ns 1.20455V/26.35411ns 1.87844V/9.09535ns
dV/dt_f 1.65161V/7.51467ns 1.18896V/17.32755ns 1.86819V/4.92526ns
R_load = 50.0
| Removed startup time: 0s 0s 0s  .
| Removed end time: 59.9ns.
[Rising Waveform]
R_fixture   = 50.0
V_fixture   = 3.3V
V_fixture_min = 2.7V
V_fixture_max = 3.6V
0s        547.3mV    718.4mV    486.3mV
1.7ns     545.8mV    718.4mV    521.8mV
1.8ns     544.2mV    718.4mV    669.9mV
2.2ns     622.3mV    718.4mV    3.245V
2.4ns     1.034V     718.5mV    3.518V
2.7ns     2.808V     717.9mV    3.58V
3.7ns     3.29V      921.4mV    3.593V
4.3ns     3.294V     2.446V     3.594V
5ns       3.296V     2.681V     3.595V
59.9ns    3.3V       2.7V       3.6V
| Removed startup time: 0s 0s 0s  .
| Removed end time: 299.9ns.
[Falling Waveform]
R_fixture   = 50.0
V_fixture   = 3.3V
V_fixture_min = 2.7V
V_fixture_max = 3.6V
0s        3.3V       2.7V       3.6V
5.1ns     3.3V       2.708V     3.512V
8.5ns     3.1V       2.7V       2.407V
11.1ns    2.641V     2.689V     1.408V
13.4ns    2.081V     2.653V     800.2mV
17.9ns    1.132V     2.506V     568.2mV
20.6ns    835.7mV    2.367V     527.6mV
38.9ns    581.1mV    1.117V     481.3mV
60.5ns    553.1mV    817.7mV    485mV
299.9ns   547.3mV    718.4mV    486.3mV
| Removed startup time: 0s 0s 0s  .
| Removed end time: 299.9ns.
[Rising Waveform]
R_fixture   = 50.0
V_fixture   = 0V
V_fixture_min = 0V
V_fixture_max = 0V
0s        74.22nV    500.4nV    82.29nV
6.1ns     10.85mV    -691.6uV   132.3mV
11.6ns    362.3mV    22.07mV    1.132V
16.4ns    942mV      117.8mV    2.169V
19.9ns    1.417V     215.6mV    2.7V
26.8ns    2.213V     496.6mV    2.982V
31ns      2.452V     699.2mV    3.043V
52.8ns    2.707V     1.657V     3.122V
75.9ns    2.741V     1.919V     3.129V
299.9ns   2.747V     2.008V     3.131V
| Removed startup time: 0s 0s 0s  .
| Removed end time: 59.9ns.
[Falling Waveform]
R_fixture   = 50.0
V_fixture   = 0V
V_fixture_min = 0V
V_fixture_max = 0V
0s        2.747V     2.008V     3.131V
1.3ns     2.748V     2.008V     3.096V
1.6ns     2.732V     2.008V     2.916V
1.9ns     2.594V     2.008V     2.339V
2.6ns     1.467V     1.998V     379.3mV
3ns       638.2mV    1.845V     65.42mV
3.4ns     161.1mV    1.544V     16.64mV
4.7ns     4.998mV    310mV      4.716mV
5.9ns     3.147mV    11.03mV    4.131mV
59.9ns    37.06uV    122.4uV    14.28uV
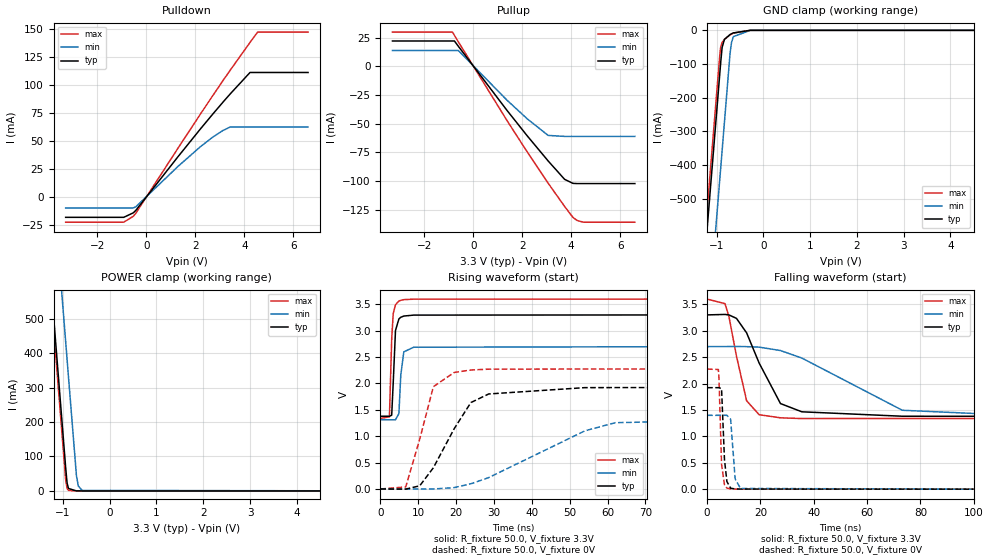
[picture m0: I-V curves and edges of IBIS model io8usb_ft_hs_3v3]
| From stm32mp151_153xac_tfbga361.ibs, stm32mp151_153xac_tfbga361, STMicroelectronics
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[Model]   io8usb_ft_hs_3v3
Model_type I/O
Polarity   Inverting
Enable   Active-Low
| CAP_THRESHOLD on pad DNFT is "UDTCAPC" :
| Rising=20.00f vddiom   Falling=80.00f vddiom
| C_comp min and max val. don't necessarily correlate with the min and max pvt
| but are the smallest and greatest pad capacitance found.
| var   typ   min   max
C_comp   9.38956pF  9.29992pF  9.39296pF
|C_comp_pullup   5.07555pF  4.79130pF  5.26010pF
|C_comp_pulldown   4.31401pF  4.50862pF  4.13286pF
Vinl = 1.08V
Vinh = 2.16V
Vmeas = 1.65V   | Reference voltage for timing measurements
Cref  = 50.0pF   | Timing specification test load capacitance value
Rref  = 100.0MOhm   | Timing specification test load resistance value
Vref  = 0V   | Timing specification test load voltage
[Model Spec]
| TIME_THRESHOLD on pin ZINV11 is "CMOS" :
| Rising=40.00f vdd   Falling=60.00f vdd
Vinl 1.36060V 1.12960V 1.47360V
Vinh 1.71640V 1.45140V 1.83040V
| variable   typ   min   max
[Temperature Range] 25.0 140.0 -40.0
| variable   typ   min   max
[Voltage Range] 3.3V 2.7V 3.6V
| variable   typ   min   max
[POWER Clamp Reference] 3.3V 2.7V 3.6V
| variable   typ   min   max
[GND Clamp Reference] 0V 0V 0V
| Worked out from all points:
|   slope of the pulldown table from 0 to 0.495 V, typ, clamps not added: 35.8 ohm
|   slope of the pullup table from 0 to 0.495 V, typ, clamps not added: 35.7 ohm
|   GND clamp passes 1 mA (typ) near -0.46 V on its own axis
|   POWER clamp passes 1 mA (typ) near -0.83 V on its own axis
|   rising waveform, R_fixture 50.0, V_fixture 3.3V: 20-80 % time 588ps typ, 600ps min, 595ps max; typ from 1.38 V to 3.3 V
|   falling waveform, R_fixture 50.0, V_fixture 3.3V: 20-80 % time 10.3ns typ, 28.2ns min, 5.48ns max; typ from 3.3 V to 1.38 V
|   rising waveform, R_fixture 50.0, V_fixture 0V: 20-80 % time 8.93ns typ, 23.8ns min, 4.7ns max; typ from 0 V to 1.92 V
|   falling waveform, R_fixture 50.0, V_fixture 0V: 20-80 % time 944ps typ, 1.14ns min, 858ps max; typ from 1.92 V to 0 V
[POWER Clamp]
-3.3V     4.079A     4.444A     4.043A
-1.46V    950.8mA    1.316A     915.5mA
-1.28V    644.8mA    1.01A      609.5mA
-1.27V    627.8mA    993.1mA    592.5mA
-1.05V    253.8mA    619.1mA    218.5mA
-940mV    66.83mA    432.1mA    31.5mA
-910mV    22.88mA    381.1mA    7.077mA
-880mV    7.117mA    330.1mA    1.59mA
-710mV    9.526uA    43.89mA    337.4nA
-670mV    2.011uA    14.27mA    46.75nA
-590mV    93.56nA    1.508mA    1.48nA
6.6V      0A         0A         0A
[GND Clamp]
-3.3V     -4.158A    -4.471A    -4.102A
-1.25V    -672.7mA   -985.8mA   -617.5mA
-1.1V     -417.7mA   -730.8mA   -362.5mA
-930mV    -128.7mA   -441.8mA   -73.47mA
-910mV    -94.71mA   -407.8mA   -49.55mA
-880mV    -50.68mA   -356.8mA   -35.8mA
-830mV    -26.73mA   -271.8mA   -26.74mA
-710mV    -12.44mA   -67.81mA   -13.64mA
-680mV    -10.24mA   -36.49mA   -11.11mA
-640mV    -7.685mA   -18.75mA   -8.114mA
-280mV    -6.923uA   -112uA     -875.7nA
6.6V      21.96nA    7.413uA    1.058nA
| variable   typ   min   max
[Pullup Reference] 3.3V 2.7V 3.6V
| variable   typ   min   max
[Pulldown Reference] 0V 0V 0V
[Pullup]
-3.3V     22.01mA    13.72mA    29.75mA
-850mV    22.01mA    13.72mA    29.75mA
-770mV    22.01mA    13.72mA    26.93mA
-610mV    17.4mA     13.72mA    21.28mA
1.38V     -38.47mA   -29.57mA   -47.31mA
2.21V     -60.71mA   -45.85mA   -74.78mA
3.06V     -82.45mA   -60.19mA   -101.8mA
3.73V     -98.4mA    -61.03mA   -122mA
4.07V     -101.9mA   -61.03mA   -131.5mA
4.25V     -102.1mA   -61.03mA   -134.3mA
4.5V      -102.1mA   -61.03mA   -135.7mA
6.6V      -102.1mA   -61.03mA   -135.7mA
[Pulldown]
-3.3V     -18.26mA   -9.99mA    -22.6mA
-930mV    -18.26mA   -9.99mA    -22.6mA
-540mV    -14.26mA   -9.827mA   -17.4mA
-440mV    -12.19mA   -8.964mA   -14.78mA
1.31V     36.52mA    27.7mA     44.27mA
2.21V     60.9mA     44.99mA    74.23mA
2.7V      73.79mA    53.31mA    90.25mA
3.12V     84.56mA    59.3mA     103.8mA
3.42V     92.04mA    62.49mA    113.2mA
4.23V     111.2mA    62.49mA    138.1mA
4.54V     111.2mA    62.49mA    147.3mA
6.6V      111.2mA    62.49mA    147.3mA
[Ramp]
dV/dt_r 1.15301V/8.92998ns 839.06358mV/23.79146ns 1.36462V/4.70072ns
dV/dt_f 1.15265V/10.32501ns 827.67813mV/28.23165ns 1.35698V/5.48262ns
R_load = 50.0
| Removed startup time: 0s 0s 0s  .
| Removed end time: 99.9ns.
[Rising Waveform]
R_fixture   = 50.0
V_fixture   = 3.3V
V_fixture_min = 2.7V
V_fixture_max = 3.6V
0s        1.379V     1.312V     1.338V
2.4ns     1.379V     1.312V     1.368V
3ns       1.398V     1.312V     2.847V
3.4ns     2.012V     1.312V     3.324V
4ns       3.004V     1.312V     3.493V
4.9ns     3.223V     1.428V     3.562V
5.4ns     3.255V     2.161V     3.577V
6.2ns     3.278V     2.599V     3.589V
8.8ns     3.296V     2.687V     3.598V
99.9ns    3.3V       2.7V       3.6V
| Removed startup time: 0s 0s 0s  .
| Removed end time: 149.9ns.
[Falling Waveform]
R_fixture   = 50.0
V_fixture   = 3.3V
V_fixture_min = 2.7V
V_fixture_max = 3.6V
0s        3.3V       2.7V       3.6V
6.7ns     3.309V     2.7V       3.513V
8.2ns     3.299V     2.701V     3.261V
11ns      3.234V     2.702V     2.518V
14.8ns    2.96V      2.699V     1.674V
19.5ns    2.388V     2.69V      1.41V
27.5ns    1.621V     2.625V     1.351V
35.5ns    1.465V     2.483V     1.337V
73.2ns    1.381V     1.494V     1.338V
149.9ns   1.379V     1.321V     1.338V
| Removed startup time: 0s 0s 0s  .
| Removed end time: 149.9ns.
[Rising Waveform]
R_fixture   = 50.0
V_fixture   = 0V
V_fixture_min = 0V
V_fixture_max = 0V
0s        35.18nV    1.962uV    48.93nV
6.7ns     -1.981mV   -3.553mV   39.16mV
10.4ns    60.05mV    -789.4uV   944.1mV
14ns      402.1mV    12.36uV    1.939V
19.5ns    1.143V     25.43mV    2.209V
23.9ns    1.638V     98.33mV    2.255V
28.6ns    1.801V     215.9mV    2.271V
54ns      1.921V     1.102V     2.274V
62ns      1.922V     1.256V     2.274V
149.9ns   1.922V     1.398V     2.274V
| Removed startup time: 0s 0s 0s  .
| Removed end time: 99.9ns.
[Falling Waveform]
R_fixture   = 50.0
V_fixture   = 0V
V_fixture_min = 0V
V_fixture_max = 0V
0s        1.922V     1.398V     2.274V
4.2ns     1.922V     1.398V     2.266V
4.4ns     1.922V     1.398V     2.145V
5.4ns     1.903V     1.399V     471.3mV
6.5ns     558.3mV    1.399V     84.88mV
7.4ns     144.5mV    1.399V     21.35mV
8.8ns     18.65mV    1.325V     5.398mV
10.5ns    3.631mV    194.7mV    1.797mV
12.5ns    2.136mV    13.39mV    796.1uV
99.9ns    4.194uV    72.68uV    207.7nV
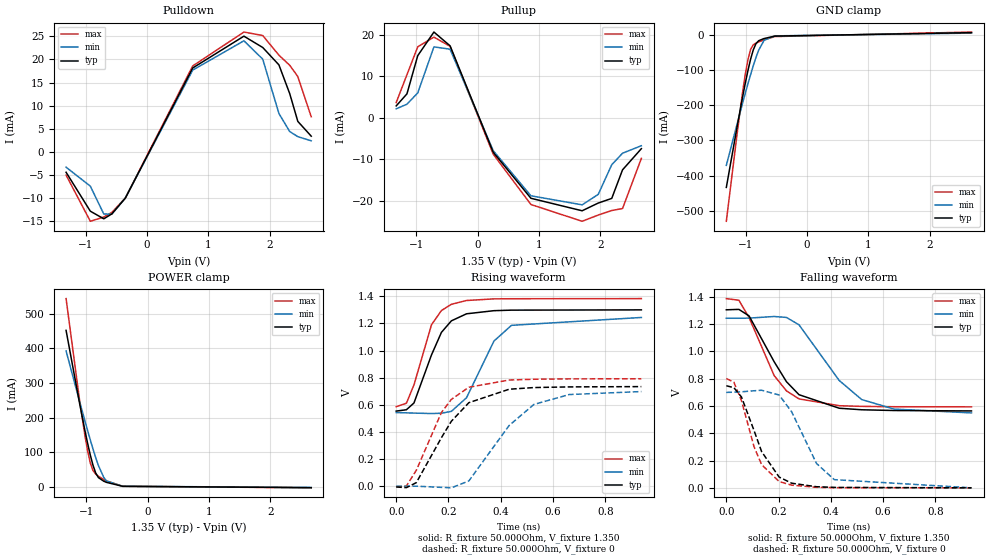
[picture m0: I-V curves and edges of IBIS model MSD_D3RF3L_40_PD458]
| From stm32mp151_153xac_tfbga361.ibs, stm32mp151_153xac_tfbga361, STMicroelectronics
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[Model] MSD_D3RF3L_40_PD458
Model_type   I/O
C_comp 2.393pF   2.308pF   2.516pF
Vinh = 810.000mV
Vinl = 540.000mV
Vmeas = 675.000mV
Vref = 675.000mV
[Model Spec]
Vinh   810.000mV   777.000mV   860.000mV
Vinl   540.000mV   507.000mV   590.000mV
Vmeas   675.000mV   642.000mV   725.000mV
Vref   675.000mV   642.000mV   725.000mV
[Temperature Range]   25.000   125.000   -40.000
[Voltage Range]   1.350V   1.283V   1.450V
[GND Clamp Reference]   0.00V   0.00V   0.00V
[Pulldown Reference]   0.00V   0.00V   0.00V
[POWER Clamp Reference]   1.350V   1.283V   1.450V
[Pullup Reference]   1.350V   1.283V   1.450V
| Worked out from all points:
|   slope of the pulldown table from 0 to 0.203 V, typ, clamps not added: 35.6 ohm
|   slope of the pullup table from 0 to 0.203 V, typ, clamps not added: 29.7 ohm
|   GND clamp passes 1 mA (typ) near -0.40 V on its own axis
|   POWER clamp passes 1 mA (typ) near -0.41 V on its own axis
|   rising waveform, R_fixture 50.000Ohm, V_fixture 1.350: 20-80 % time 89.2ps typ, 109ps min, 76.5ps max; typ from 0.554 V to 1.3 V
|   rising waveform, R_fixture 50.000Ohm, V_fixture 0: 20-80 % time 142ps typ, 167ps min, 122ps max; typ from -0.005 V to 0.734 V
|   falling waveform, R_fixture 50.000Ohm, V_fixture 1.350: 20-80 % time 139ps typ, 168ps min, 118ps max; typ from 1.3 V to 0.564 V
|   falling waveform, R_fixture 50.000Ohm, V_fixture 0: 20-80 % time 93.7ps typ, 111ps min, 80.5ps max; typ from 0.748 V to 0 V
[GND Clamp]
-1.318V   -433.4mA   -370.8mA   -529.5mA
-1.142V   -261.1mA   -253.1mA   -280.7mA
-1.055V   -178.6mA   -195.6mA   -165.7mA
-1.011V   -139.5mA   -167.5mA   -114.5mA
-966.7mV  -102.7mA   -140mA     -71.69mA
-922.7mV  -69.83mA   -113.5mA   -42.04mA
-878.8mV  -43.2mA    -88.17mA   -28.64mA
-834.9mV  -25.59mA   -64.74mA   -23.69mA
-790.9mV  -17.08mA   -44.07mA   -20.49mA
-703mV    -10.94mA   -16.13mA   -14.83mA
-527.3mV  -3.964mA   -3.359mA   -5.286mA
2.68V     5.803mA    4.518mA    7.521mA
[Power Clamp]
-1.33V    452.5mA    393mA      544.4mA
-1.111V   242.2mA    247.4mA    251.2mA
-1.023V   162.6mA    190.5mA    148.3mA
-978.8mV  125.4mA    162.5mA    103.8mA
-934.9mV  91.31mA    135.3mA    68.32mA
-890.9mV  61.93mA    108.9mA    46.71mA
-847mV    39.6mA     84.01mA    36.22mA
-803mV    26.26mA    61.23mA    30.15mA
-715.1mV  15.61mA    26.48mA    20.68mA
-671.2mV  12.4mA     16.4mA     16.54mA
-407.6mV  894uA      1.169mA    1.092mA
2.668V    -2.917mA   -2.431mA   -3.468mA
[Pulldown]
-1.318V   -4.4mA     -3.3mA     -5mA
-922.7mV  -12.81mA   -7.4mA     -14.99mA
-703mV    -14.46mA   -13.42mA   -14.07mA
-571.2mV  -13.39mA   -13.45mA   -13.07mA
-351.5mV  -9.981mA   -9.957mA   -9.949mA
747mV     18.14mA    17.68mA    18.58mA
1.582V    25.02mA    24.02mA    25.91mA
1.889V    22.57mA    20.05mA    25.16mA
2.153V    18.81mA    8.3mA      20.9mA
2.329V    12.6mA     4.4mA      18.73mA
2.461V    6.6mA      3.3mA      16.3mA
2.68V     3.4mA      2.4mA      7.6mA
[Pullup]
-1.33V    2.9mA      2.205mA    3.707mA
-1.155V   5.8mA      3.31mA     10.41mA
-978.8mV  15mA       6.025mA    17.13mA
-715.1mV  20.69mA    17.11mA    19.47mA
-451.5mV  17.37mA    16.56mA    17.25mA
251.5mV   -8.249mA   -7.87mA    -8.718mA
866.7mV   -19.35mA   -18.75mA   -20.85mA
1.702V    -22.36mA   -20.93mA   -24.89mA
1.965V    -20.5mA    -18.41mA   -23.39mA
2.185V    -19.38mA   -11.27mA   -22.3mA
2.361V    -12.5mA    -8.49mA    -21.82mA
2.668V    -7.4mA     -6.695mA   -9.748mA
[Ramp]
R_load=50.000Ohm
dV/dt_r   441.270mV/116.000ps  419.639mV/139.500ps  474.510mV/100.000ps
dV/dt_f   441.270mV/116.000ps  419.639mV/141.000ps  474.510mV/100.000ps
[Rising waveform]
R_fixture=50.000Ohm
V_fixture=1.350
V_fixture_min=1.283
V_fixture_max=1.450
0s        554mV      543.1mV    586.4mV
39ps      563.8mV    541mV      612mV
68ps      613.9mV    539.2mV    747.3mV
135ps     967.8mV    535.8mV    1.19V
173ps     1.134V     538.1mV    1.295V
211ps     1.219V     552mV      1.341V
269ps     1.271V     652.3mV    1.369V
374ps     1.294V     1.07V      1.381V
441ps     1.298V     1.186V     1.382V
938ps     1.3V       1.244V     1.383V
[Rising waveform]
R_fixture=50.000Ohm
V_fixture=0
0s        -5.264mV   812.8uV    -4.642mV
39ps      -10.36mV   921.1uV    1.385mV
77ps      26.66mV    409.1uV    117.8mV
173ps     358mV      -8.189mV   543.8mV
211ps     479.1mV    -11.71mV   640.3mV
278ps     616mV      39.21mV    729.7mV
432ps     715mV      447.7mV    782.9mV
527ps     727.4mV    603.2mV    788.6mV
662ps     732.2mV    675.9mV    791.3mV
938ps     734.4mV    697.9mV    792.3mV
[Falling waveform]
R_fixture=50.000Ohm
V_fixture=1.350
V_fixture_min=1.283
V_fixture_max=1.450
0s        1.305V     1.243V     1.387V
48ps      1.308V     1.243V     1.375V
87ps      1.26V      1.244V     1.248V
183ps     924.3mV    1.256V     822.7mV
230ps     778.1mV    1.249V     710.7mV
278ps     682.7mV    1.195V     651.9mV
432ps     583.4mV    786.6mV    602mV
518ps     572.2mV    646.9mV    597.2mV
642ps     566.7mV    577.1mV    594.5mV
938ps     563.7mV    549.2mV    593.6mV
[Falling waveform]
R_fixture=50.000Ohm
V_fixture=0
0s        748.3mV    699.7mV    801.4mV
29ps      733.9mV    700.9mV    773.6mV
58ps      665.7mV    703.8mV    638.6mV
106ps     420.1mV    711.4mV    301.2mV
135ps     265.5mV    715.3mV    170mV
202ps     79mV       680.5mV    46.24mV
250ps     34.04mV    557mV      19.54mV
345ps     8.098mV    178.6mV    3.841mV
413ps     3.159mV    60.09mV    1.219mV
938ps     9.833uV    145.1uV    7.355uV
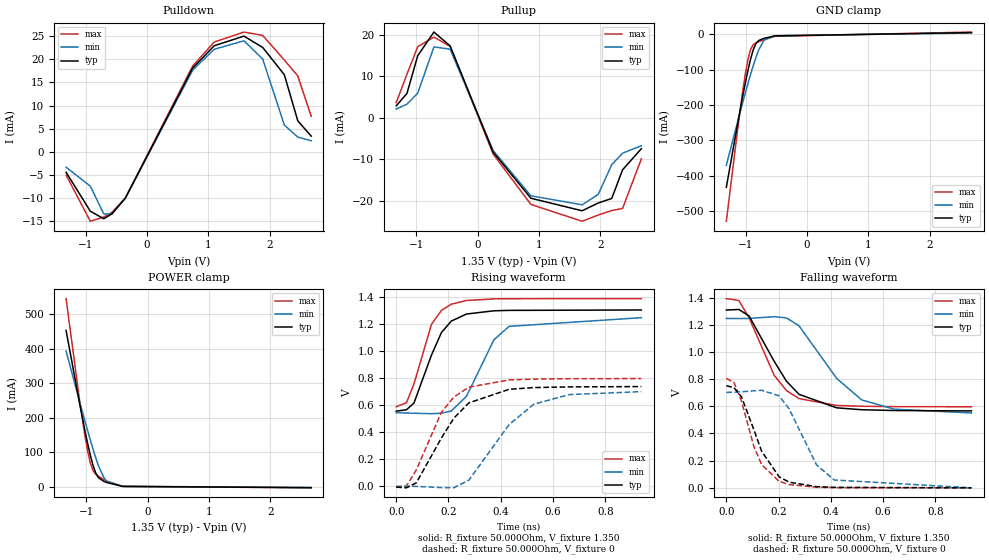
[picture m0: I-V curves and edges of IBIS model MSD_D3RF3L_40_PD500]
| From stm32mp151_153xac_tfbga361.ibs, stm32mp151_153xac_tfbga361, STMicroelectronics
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[Model] MSD_D3RF3L_40_PD500
Model_type   I/O
C_comp 2.410pF   2.326pF   2.533pF
Vinh = 810.000mV
Vinl = 540.000mV
Vmeas = 675.000mV
Vref = 675.000mV
[Model Spec]
Vinh   810.000mV   777.000mV   860.000mV
Vinl   540.000mV   507.000mV   590.000mV
Vmeas   675.000mV   642.000mV   725.000mV
Vref   675.000mV   642.000mV   725.000mV
[Temperature Range]   25.000   125.000   -40.000
[Voltage Range]   1.350V   1.283V   1.450V
[GND Clamp Reference]   0.00V   0.00V   0.00V
[Pulldown Reference]   0.00V   0.00V   0.00V
[POWER Clamp Reference]   1.350V   1.283V   1.450V
[Pullup Reference]   1.350V   1.283V   1.450V
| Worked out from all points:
|   slope of the pulldown table from 0 to 0.203 V, typ, clamps not added: 35.7 ohm
|   slope of the pullup table from 0 to 0.203 V, typ, clamps not added: 29.7 ohm
|   GND clamp passes 1 mA (typ) near -0.40 V on its own axis
|   POWER clamp passes 1 mA (typ) near -0.41 V on its own axis
|   rising waveform, R_fixture 50.000Ohm, V_fixture 1.350: 20-80 % time 89.2ps typ, 109ps min, 76.6ps max; typ from 0.556 V to 1.3 V
|   rising waveform, R_fixture 50.000Ohm, V_fixture 0: 20-80 % time 143ps typ, 168ps min, 123ps max; typ from -0.005 V to 0.738 V
|   falling waveform, R_fixture 50.000Ohm, V_fixture 1.350: 20-80 % time 141ps typ, 169ps min, 119ps max; typ from 1.31 V to 0.566 V
|   falling waveform, R_fixture 50.000Ohm, V_fixture 0: 20-80 % time 94.3ps typ, 112ps min, 81.3ps max; typ from 0.752 V to 0 V
[GND Clamp]
-1.318V   -433.5mA   -370.9mA   -529.7mA
-1.142V   -261.2mA   -253.2mA   -280.9mA
-1.055V   -178.7mA   -195.7mA   -165.8mA
-1.011V   -139.6mA   -167.6mA   -114.7mA
-966.7mV  -102.7mA   -140.1mA   -71.8mA
-922.7mV  -69.9mA    -113.5mA   -42.14mA
-878.8mV  -43.27mA   -88.23mA   -28.74mA
-834.9mV  -25.65mA   -64.79mA   -23.77mA
-790.9mV  -17.14mA   -44.12mA   -20.57mA
-703mV    -10.99mA   -16.17mA   -14.89mA
-527.3mV  -3.983mA   -3.376mA   -5.312mA
2.68V     5.315mA    4.144mA    6.889mA
[Power Clamp]
-1.33V    452.7mA    393.1mA    544.7mA
-1.111V   242.2mA    247.6mA    251.3mA
-1.023V   162.6mA    190.6mA    148.4mA
-978.8mV  125.5mA    162.7mA    103.9mA
-934.9mV  91.39mA    135.4mA    68.44mA
-890.9mV  62.01mA    109mA      46.81mA
-847mV    39.69mA    84.09mA    36.32mA
-803mV    26.33mA    61.28mA    30.23mA
-715.1mV  15.66mA    26.52mA    20.75mA
-671.2mV  12.45mA    16.44mA    16.6mA
-407.6mV  904uA      1.178mA    1.103mA
2.668V    -2.674mA   -2.229mA   -3.179mA
[Pulldown]
-1.318V   -4.4mA     -3.3mA     -5mA
-922.7mV  -12.81mA   -7.4mA     -14.99mA
-703mV    -14.45mA   -13.41mA   -14.07mA
-571.2mV  -13.39mA   -13.44mA   -13.07mA
-351.5mV  -9.983mA   -9.966mA   -9.958mA
747mV     18.13mA    17.69mA    18.58mA
1.098V    22.94mA    22.18mA    23.74mA
1.582V    25.02mA    24.01mA    25.9mA
1.889V    22.57mA    20.05mA    25.16mA
2.241V    16.68mA    5.8mA      19.86mA
2.461V    6.7mA      3.2mA      16.4mA
2.68V     3.4mA      2.4mA      7.7mA
[Pullup]
-1.33V    2.9mA      2.152mA    3.679mA
-1.155V   5.9mA      3.31mA     10.51mA
-978.8mV  15mA       5.977mA    17.17mA
-715.1mV  20.69mA    17.11mA    19.47mA
-451.5mV  17.37mA    16.56mA    17.25mA
251.5mV   -8.25mA    -7.87mA    -8.718mA
866.7mV   -19.34mA   -18.75mA   -20.84mA
1.702V    -22.36mA   -20.93mA   -24.89mA
1.965V    -20.49mA   -18.41mA   -23.39mA
2.185V    -19.39mA   -11.25mA   -22.3mA
2.361V    -12.5mA    -8.49mA    -21.81mA
2.668V    -7.4mA     -6.695mA   -9.848mA
[Ramp]
R_load=50.000Ohm
dV/dt_r   442.830mV/116.500ps  420.839mV/139.500ps  476.640mV/100.000ps
dV/dt_f   442.830mV/117.000ps  420.839mV/142.000ps  476.640mV/100.500ps
[Rising waveform]
R_fixture=50.000Ohm
V_fixture=1.350
V_fixture_min=1.283
V_fixture_max=1.450
0s        556.4mV    544.7mV    589.4mV
39ps      566.2mV    542.6mV    617.6mV
68ps      616.5mV    540.7mV    757.8mV
135ps     970.9mV    537.6mV    1.198V
173ps     1.137V     540.9mV    1.301V
211ps     1.222V     557.6mV    1.347V
269ps     1.274V     666.7mV    1.374V
374ps     1.298V     1.084V     1.386V
432ps     1.301V     1.183V     1.387V
938ps     1.304V     1.247V     1.388V
[Rising waveform]
R_fixture=50.000Ohm
V_fixture=0
0s        -5.263mV   837uV      -4.884mV
39ps      -10.36mV   915.5uV    2.73mV
77ps      26.65mV    295.7uV    122.2mV
173ps     358.2mV    -8.734mV   548.1mV
221ps     505.7mV    -9.372mV   661.5mV
278ps     617.4mV    46.2mV     733.3mV
432ps     717.7mV    457.1mV    787.2mV
527ps     730.5mV    608.2mV    793.2mV
662ps     735.6mV    678.7mV    796.1mV
938ps     737.9mV    700.5mV    797.1mV
[Falling waveform]
R_fixture=50.000Ohm
V_fixture=1.350
V_fixture_min=1.283
V_fixture_max=1.450
0s        1.309V     1.247V     1.393V
48ps      1.313V     1.246V     1.379V
87ps      1.265V     1.247V     1.252V
183ps     931.7mV    1.26V      828.4mV
230ps     785mV      1.251V     716.1mV
278ps     688.5mV    1.193V     657mV
422ps     589mV      805.8mV    606.7mV
518ps     575mV      647.2mV    600.5mV
642ps     569.2mV    579.2mV    597.7mV
938ps     566.1mV    551mV      596.8mV
[Falling waveform]
R_fixture=50.000Ohm
V_fixture=0
0s        751.8mV    702.4mV    806.2mV
29ps      737.6mV    703.8mV    776.3mV
58ps      669.7mV    706.9mV    637.4mV
106ps     424.4mV    714.7mV    300.7mV
135ps     269.5mV    718mV      171mV
202ps     81.33mV    677.4mV    47.47mV
240ps     41.91mV    582.2mV    24.25mV
345ps     8.678mV    169.5mV    4.17mV
413ps     3.449mV    57.6mV     1.366mV
938ps     15.69uV    158uV      9.095uV
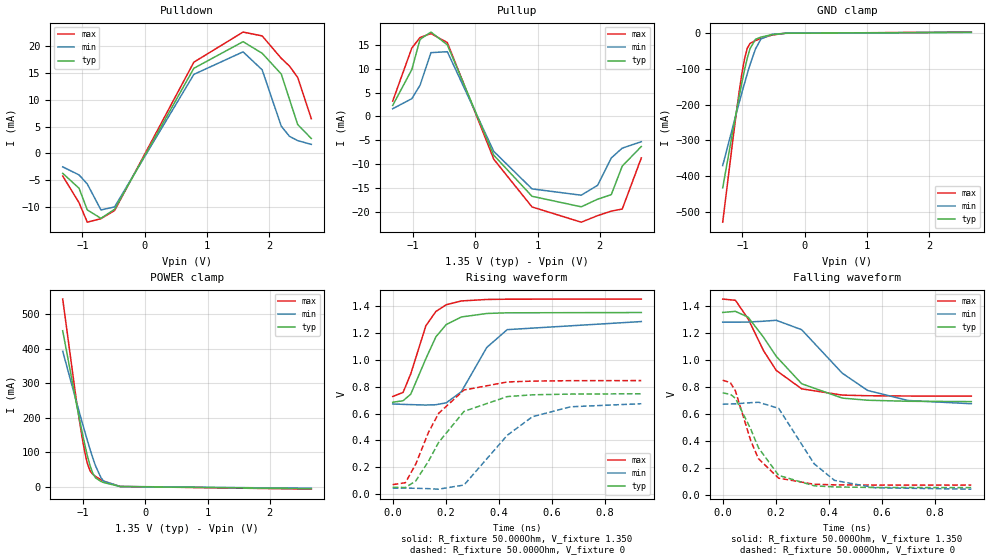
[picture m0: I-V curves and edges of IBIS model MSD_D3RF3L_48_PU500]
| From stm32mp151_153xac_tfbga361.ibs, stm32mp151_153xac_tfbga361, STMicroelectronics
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[Model] MSD_D3RF3L_48_PU500
Model_type   I/O
C_comp 2.412pF   2.328pF   2.536pF
Vinh = 810.000mV
Vinl = 540.000mV
Vmeas = 675.000mV
Vref = 675.000mV
[Model Spec]
Vinh   810.000mV   777.000mV   860.000mV
Vinl   540.000mV   507.000mV   590.000mV
Vmeas   675.000mV   642.000mV   725.000mV
Vref   675.000mV   642.000mV   725.000mV
[Temperature Range]   25.000   125.000   -40.000
[Voltage Range]   1.350V   1.283V   1.450V
[GND Clamp Reference]   0.00V   0.00V   0.00V
[Pulldown Reference]   0.00V   0.00V   0.00V
[POWER Clamp Reference]   1.350V   1.283V   1.450V
[Pullup Reference]   1.350V   1.283V   1.450V
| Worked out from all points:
|   slope of the pulldown table from 0 to 0.203 V, typ, clamps not added: 42.2 ohm
|   slope of the pullup table from 0 to 0.203 V, typ, clamps not added: 34.5 ohm
|   GND clamp passes 1 mA (typ) near -0.40 V on its own axis
|   POWER clamp passes 1 mA (typ) near -0.41 V on its own axis
|   rising waveform, R_fixture 50.000Ohm, V_fixture 1.350: 20-80 % time 91.6ps typ, 115ps min, 76.5ps max; typ from 0.684 V to 1.35 V
|   rising waveform, R_fixture 50.000Ohm, V_fixture 0: 20-80 % time 144ps typ, 176ps min, 122ps max; typ from 0.053 V to 0.747 V
|   falling waveform, R_fixture 50.000Ohm, V_fixture 1.350: 20-80 % time 161ps typ, 193ps min, 129ps max; typ from 1.35 V to 0.694 V
|   falling waveform, R_fixture 50.000Ohm, V_fixture 0: 20-80 % time 105ps typ, 123ps min, 86.4ps max; typ from 0.759 V to 0.057 V
[GND Clamp]
-1.318V   -433.4mA   -370.8mA   -529.6mA
-1.142V   -261.1mA   -253.1mA   -280.9mA
-1.055V   -178.7mA   -195.6mA   -165.8mA
-1.011V   -139.5mA   -167.5mA   -114.6mA
-966.7mV  -102.8mA   -140.1mA   -71.78mA
-922.7mV  -69.86mA   -113.4mA   -42.13mA
-878.8mV  -43.23mA   -88.18mA   -28.72mA
-790.9mV  -17.1mA    -44.08mA   -20.55mA
-703mV    -10.97mA   -16.13mA   -14.88mA
-527.3mV  -3.968mA   -3.356mA   -5.305mA
-307.6mV  -123.2uA   -182.6uA   -113.4uA
2.68V     2.644mA    2.247mA    3.128mA
[Power Clamp]
-1.33V    452.9mA    393.4mA    544.7mA
-1.111V   242.3mA    247.7mA    251.3mA
-1.023V   162.7mA    190.7mA    148.5mA
-978.8mV  125.6mA    162.8mA    103.9mA
-934.9mV  91.45mA    135.5mA    68.48mA
-890.9mV  62.07mA    109.1mA    46.85mA
-847mV    39.74mA    84.18mA    36.35mA
-803mV    26.37mA    61.36mA    30.26mA
-715.1mV  15.7mA     26.59mA    20.77mA
-671.2mV  12.49mA    16.49mA    16.61mA
-407.6mV  917.9uA    1.201mA    1.111mA
2.668V    -5.217mA   -4.179mA   -6.701mA
[Pulldown]
-1.318V   -3.7mA     -2.5mA     -4.2mA
-1.055V   -6.5mA     -4mA       -9.2mA
-922.7mV  -10.54mA   -5.7mA     -12.83mA
-703mV    -12.11mA   -10.54mA   -12.17mA
-483.3mV  -10.41mA   -9.971mA   -10.65mA
790.9mV   15.91mA    14.77mA    17.05mA
1.582V    20.88mA    18.98mA    22.67mA
1.889V    18.72mA    15.63mA    21.96mA
2.197V    14.83mA    5.1mA      17.77mA
2.329V    10.1mA     3.2mA      16.32mA
2.461V    5.4mA      2.4mA      14.2mA
2.68V     2.8mA      1.7mA      6.5mA
[Pullup]
-1.33V    2.3mA      1.605mA    3.207mA
-1.023V   9.8mA      3.715mA    14.3mA
-890.9mV  16.12mA    6.508mA    16.51mA
-715.1mV  17.65mA    13.35mA    17.34mA
-451.5mV  14.98mA    13.54mA    15.46mA
295.4mV   -8.125mA   -7.33mA    -8.965mA
910.6mV   -16.72mA   -15.17mA   -18.95mA
1.702V    -18.92mA   -16.49mA   -22.14mA
1.965V    -17.33mA   -14.42mA   -20.77mA
2.185V    -16.37mA   -8.694mA   -19.82mA
2.361V    -10.4mA    -6.643mA   -19.39mA
2.668V    -6.3mA     -5.295mA   -8.693mA
[Ramp]
R_load=50.000Ohm
dV/dt_r   403.968mV/118.500ps  371.793mV/146.500ps  445.377mV/99.500ps
dV/dt_f   403.938mV/133.000ps  371.733mV/161.000ps  445.377mV/108.500ps
[Rising waveform]
R_fixture=50.000Ohm
V_fixture=1.350
V_fixture_min=1.283
V_fixture_max=1.450
0s        683.6mV    670.9mV    726.9mV
39ps      695.1mV    668.3mV    756.5mV
68ps      743.1mV    666.2mV    894mV
125ps     1.007V     663.1mV    1.251V
163ps     1.17V      665.5mV    1.358V
202ps     1.261V     679.7mV    1.408V
259ps     1.317V     761.9mV    1.436V
355ps     1.343V     1.091V     1.447V
432ps     1.348V     1.223V     1.449V
938ps     1.35V      1.283V     1.45V
[Rising waveform]
R_fixture=50.000Ohm
V_fixture=0
0s        52.73mV    45.93mV    72mV
48ps      50.63mV    45.89mV    86.59mV
87ps      99.33mV    45.12mV    224.7mV
135ps     246.1mV    42.32mV    460.2mV
173ps     385mV      38.49mV    600.8mV
269ps     616mV      69.16mV    774.5mV
432ps     725.9mV    438.2mV    834.5mV
527ps     739mV      576.4mV    840.8mV
671ps     744.6mV    650.2mV    844mV
938ps     746.9mV    672.9mV    844.7mV
[Falling waveform]
R_fixture=50.000Ohm
V_fixture=1.350
V_fixture_min=1.283
V_fixture_max=1.450
0s        1.354V     1.282V     1.453V
48ps      1.362V     1.282V     1.444V
96ps      1.319V     1.283V     1.306V
154ps     1.17V      1.289V     1.071V
202ps     1.029V     1.296V     924.9mV
298ps     825.8mV    1.226V     788.2mV
451ps     719.9mV    904.4mV    742.1mV
547ps     704mV      776.1mV    737.3mV
700ps     696.3mV    702mV      735.2mV
938ps     694mV      678.1mV    734.6mV
[Falling waveform]
R_fixture=50.000Ohm
V_fixture=0
0s        758.5mV    675.1mV    852.3mV
29ps      747.8mV    676.3mV    834.1mV
48ps      718.7mV    677.8mV    772.5mV
106ps     489.5mV    685.9mV    403mV
135ps     351.6mV    689.1mV    270.7mV
211ps     147.6mV    644.2mV    127.2mV
345ps     70.63mV    233.5mV    81.99mV
422ps     62.22mV    110.5mV    77.71mV
575ps     57.95mV    56mV       76.2mV
938ps     57.27mV    45.67mV    75.92mV
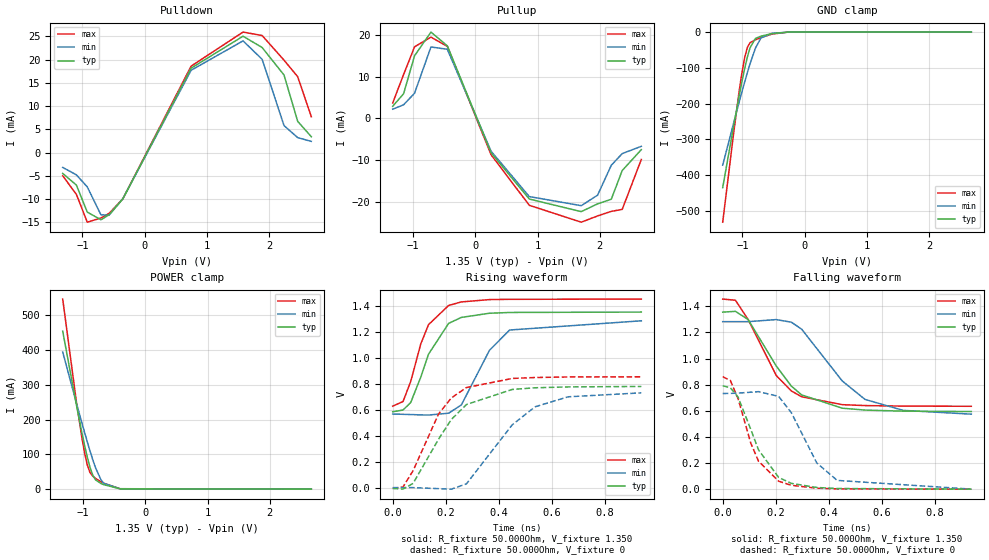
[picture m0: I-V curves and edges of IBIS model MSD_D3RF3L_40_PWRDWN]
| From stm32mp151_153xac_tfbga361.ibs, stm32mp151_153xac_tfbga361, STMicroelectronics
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[Model] MSD_D3RF3L_40_PWRDWN
Model_type   I/O
C_comp 2.572pF   2.485pF   2.698pF
Vinh = 810.000mV
Vinl = 540.000mV
Vmeas = 675.000mV
Vref = 675.000mV
[Model Spec]
Vinh   810.000mV   777.000mV   860.000mV
Vinl   540.000mV   507.000mV   590.000mV
Vmeas   675.000mV   642.000mV   725.000mV
Vref   675.000mV   642.000mV   725.000mV
[Temperature Range]   25.000   125.000   -40.000
[Voltage Range]   1.350V   1.283V   1.450V
[GND Clamp Reference]   0.00V   0.00V   0.00V
[Pulldown Reference]   0.00V   0.00V   0.00V
[POWER Clamp Reference]   1.350V   1.283V   1.450V
[Pullup Reference]   1.350V   1.283V   1.450V
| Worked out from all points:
|   slope of the pulldown table from 0 to 0.203 V, typ, clamps not added: 35.7 ohm
|   slope of the pullup table from 0 to 0.203 V, typ, clamps not added: 29.7 ohm
|   GND clamp passes 1 mA (typ) near -0.40 V on its own axis
|   POWER clamp passes 1 mA (typ) near -0.41 V on its own axis
|   rising waveform, R_fixture 50.000Ohm, V_fixture 1.350: 20-80 % time 91.4ps typ, 112ps min, 79.9ps max; typ from 0.584 V to 1.35 V
|   rising waveform, R_fixture 50.000Ohm, V_fixture 0: 20-80 % time 151ps typ, 173ps min, 133ps max; typ from -0.006 V to 0.778 V
|   falling waveform, R_fixture 50.000Ohm, V_fixture 1.350: 20-80 % time 154ps typ, 180ps min, 134ps max; typ from 1.35 V to 0.594 V
|   falling waveform, R_fixture 50.000Ohm, V_fixture 0: 20-80 % time 101ps typ, 118ps min, 89.3ps max; typ from 0.792 V to 0 V
[GND Clamp]
-1.318V   -435mA     -372.2mA   -531.7mA
-1.142V   -262.4mA   -254.2mA   -282.5mA
-1.055V   -179.8mA   -196.6mA   -167.2mA
-1.011V   -140.5mA   -168.4mA   -116mA
-966.7mV  -103.7mA   -140.9mA   -72.98mA
-922.7mV  -70.73mA   -114.2mA   -43.23mA
-878.8mV  -44.02mA   -88.84mA   -29.72mA
-790.9mV  -17.74mA   -44.62mA   -21.37mA
-703mV    -11.46mA   -16.55mA   -15.5mA
-527.3mV  -4.197mA   -3.553mA   -5.598mA
-263.6mV  -40.6uA    -78.9uA    -28.72uA
2.68V     28.25nA    782nA      4.355nA
[Power Clamp]
-1.33V    454.4mA    394.7mA    546.8mA
-1.111V   243.5mA    248.7mA    252.9mA
-1.023V   163.7mA    191.5mA    149.8mA
-978.8mV  126.5mA    163.6mA    105.2mA
-934.9mV  92.34mA    136.2mA    69.61mA
-890.9mV  62.88mA    109.8mA    47.89mA
-847mV    40.47mA    84.8mA     37.29mA
-803mV    27.03mA    61.92mA    31.1mA
-715.1mV  16.21mA    27.03mA    21.42mA
-671.2mV  12.92mA    16.88mA    17.18mA
-407.6mV  989.1uA    1.283mA    1.2mA
2.668V    -48.24nA   -903.5nA   -4.583nA
[Pulldown]
-1.318V   -4.5mA     -3.2mA     -5mA
-1.098V   -7mA       -4.8mA     -9mA
-922.7mV  -12.81mA   -7.4mA     -14.98mA
-703mV    -14.46mA   -13.41mA   -14.08mA
-571.2mV  -13.38mA   -13.44mA   -13.08mA
-351.5mV  -9.983mA   -9.959mA   -9.952mA
747mV     18.14mA    17.69mA    18.58mA
1.582V    25.02mA    24.01mA    25.9mA
1.889V    22.58mA    20.05mA    25.16mA
2.241V    16.67mA    5.8mA      19.86mA
2.461V    6.7mA      3.2mA      16.3mA
2.68V     3.4mA      2.4mA      7.7mA
[Pullup]
-1.33V    2.9mA      2.205mA    3.679mA
-1.155V   5.9mA      3.257mA    10.51mA
-978.8mV  15mA       6.025mA    17.15mA
-715.1mV  20.68mA    17.11mA    19.47mA
-451.5mV  17.37mA    16.56mA    17.25mA
251.5mV   -8.249mA   -7.869mA   -8.718mA
866.7mV   -19.34mA   -18.75mA   -20.84mA
1.702V    -22.36mA   -20.93mA   -24.89mA
1.965V    -20.49mA   -18.41mA   -23.39mA
2.185V    -19.39mA   -11.25mA   -22.3mA
2.361V    -12.5mA    -8.443mA   -21.82mA
2.668V    -7.5mA     -6.7mA     -9.848mA
[Ramp]
R_load=50.000Ohm
dV/dt_r   460.500mV/121.000ps  434.129mV/144.500ps  500.520mV/106.500ps
dV/dt_f   460.500mV/127.500ps  434.129mV/151.500ps  500.520mV/112.500ps
[Rising waveform]
R_fixture=50.000Ohm
V_fixture=1.350
V_fixture_min=1.283
V_fixture_max=1.450
0s        583.7mV    566.4mV    626.5mV
39ps      597.1mV    564.2mV    662.6mV
68ps      655.2mV    562.3mV    816.8mV
106ps     850.5mV    559.8mV    1.106V
135ps     1.026V     558.4mV    1.253V
211ps     1.263V     572.7mV    1.401V
259ps     1.309V     636.2mV    1.428V
365ps     1.341V     1.056V     1.446V
441ps     1.347V     1.212V     1.448V
938ps     1.35V      1.283V     1.45V
[Rising waveform]
R_fixture=50.000Ohm
V_fixture=0
0s        -5.879mV   769.3uV    -5.417mV
39ps      -10.23mV   939.1uV    5.838mV
77ps      33.22mV    592.2uV    131.4mV
173ps     373.2mV    -7.388mV   566.8mV
221ps     523.7mV    -11.19mV   689.7mV
278ps     639.4mV    29.35mV    769.6mV
451ps     755.3mV    483.5mV    839.8mV
537ps     768.1mV    621.9mV    847mV
662ps     774.8mV    698.8mV    851.2mV
938ps     778.3mV    729.1mV    852.5mV
[Falling waveform]
R_fixture=50.000Ohm
V_fixture=1.350
V_fixture_min=1.283
V_fixture_max=1.450
0s        1.355V     1.282V     1.455V
48ps      1.361V     1.282V     1.446V
96ps      1.298V     1.282V     1.298V
202ps     942.8mV    1.298V     869.9mV
259ps     788.5mV    1.278V     751.9mV
298ps     721.4mV    1.224V     706.9mV
451ps     619.8mV    828.2mV    646.8mV
537ps     605.3mV    686.8mV    639.8mV
681ps     597.2mV    603.1mV    635.7mV
938ps     594.1mV    574.1mV    634.4mV
[Falling waveform]
R_fixture=50.000Ohm
V_fixture=0
0s        791.5mV    732.1mV    861.2mV
29ps      775.8mV    733mV      831.4mV
58ps      704.9mV    735.2mV    691.9mV
106ps     457.1mV    742.2mV    352.2mV
135ps     301.4mV    746.4mV    214.5mV
211ps     89.97mV    710.2mV    60.95mV
259ps     44.24mV    585.3mV    29.59mV
355ps     12.85mV    200.3mV    7.342mV
432ps     5.03mV     66.95mV    2.449mV
938ps     -3.277uV   340.2uV    -2.256uV
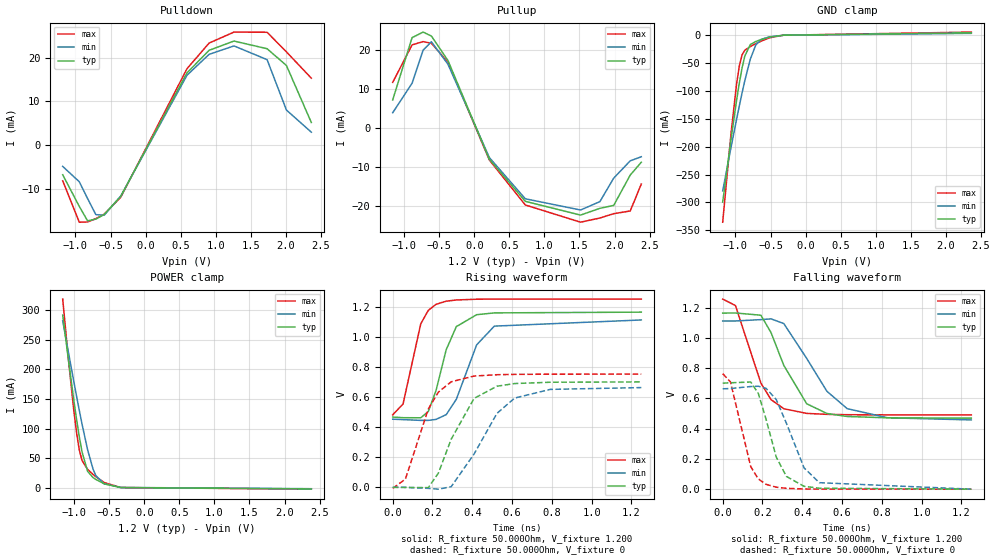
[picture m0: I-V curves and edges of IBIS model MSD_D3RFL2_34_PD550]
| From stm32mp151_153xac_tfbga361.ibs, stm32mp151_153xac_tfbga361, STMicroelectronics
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[Model] MSD_D3RFL2_34_PD550
Model_type   I/O
C_comp 2.431pF   2.345pF   2.556pF
Vinh = 820.000mV
Vinl = 380.000mV
Vmeas = 600.000mV
Vref = 600.000mV
[Model Spec]
Vinh   820.000mV   790.000mV   870.000mV
Vinl   380.000mV   350.000mV   430.000mV
Vmeas   600.000mV   570.000mV   650.000mV
Vref   600.000mV   570.000mV   650.000mV
[Temperature Range]   25.000   125.000   -40.000
[Voltage Range]   1.200V   1.140V   1.300V
[GND Clamp Reference]   0.00V   0.00V   0.00V
[Pulldown Reference]   0.00V   0.00V   0.00V
[POWER Clamp Reference]   1.200V   1.140V   1.300V
[Pullup Reference]   1.200V   1.140V   1.300V
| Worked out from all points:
|   slope of the pulldown table from 0 to 0.18 V, typ, clamps not added: 31.3 ohm
|   slope of the pullup table from 0 to 0.18 V, typ, clamps not added: 26.5 ohm
|   GND clamp passes 1 mA (typ) near -0.40 V on its own axis
|   POWER clamp passes 1 mA (typ) near -0.41 V on its own axis
|   rising waveform, R_fixture 50.000Ohm, V_fixture 1.200: 20-80 % time 90.7ps typ, 117ps min, 77.4ps max; typ from 0.468 V to 1.17 V
|   rising waveform, R_fixture 50.000Ohm, V_fixture 0: 20-80 % time 145ps typ, 176ps min, 124ps max; typ from 0.001 V to 0.702 V
|   falling waveform, R_fixture 50.000Ohm, V_fixture 1.200: 20-80 % time 145ps typ, 191ps min, 120ps max; typ from 1.17 V to 0.47 V
|   falling waveform, R_fixture 50.000Ohm, V_fixture 0: 20-80 % time 94.7ps typ, 121ps min, 80.9ps max; typ from 0.701 V to 0 V
[GND Clamp]
-1.182V   -299.4mA   -279.4mA   -335.5mA
-1.064V   -187.2mA   -201.7mA   -177.2mA
-984.9mV  -117.7mA   -151.5mA   -88.38mA
-945.5mV  -86.38mA   -127.3mA   -55.57mA
-906.1mV  -58.98mA   -103.8mA   -35.45mA
-866.7mV  -37.48mA   -81.61mA   -27.05mA
-787.9mV  -16.83mA   -42.88mA   -20.43mA
-709.1mV  -11.34mA   -17.45mA   -15.32mA
-630.3mV  -7.809mA   -7.49mA    -10.62mA
-512.1mV  -3.532mA   -3.013mA   -4.68mA
-315.1mV  -161.1uA   -227.4uA   -151.1uA
2.364V    4.162mA    3.192mA    5.446mA
[Power Clamp]
-1.164V   292.2mA    282.4mA    319.1mA
-1.085V   218.5mA    230.7mA    219.9mA
-1.006V   148.3mA    179.9mA    131mA
-966.7mV  115.8mA    155mA      93.19mA
-927.3mV  85.99mA    130.7mA    63.83mA
-887.9mV  60.26mA    107.3mA    45.72mA
-809.1mV  27.71mA    64.21mA    31.02mA
-730.3mV  16.94mA    31.06mA    22.31mA
-690.9mV  13.86mA    20.24mA    18.46mA
-572.7mV  6.594mA    6.506mA    8.718mA
-336.4mV  182.6uA    351.4uA    213.2uA
2.382V    -2.141mA   -1.766mA   -2.539mA
[Pulldown]
-1.182V   -6.7mA     -4.8mA     -8.1mA
-945.5mV  -13.91mA   -8.3mA     -17.51mA
-827.3mV  -17.2mA    -12.13mA   -17.46mA
-709.1mV  -16.81mA   -15.79mA   -16.7mA
-590.9mV  -15.77mA   -15.93mA   -15.7mA
-354.6mV  -11.63mA   -11.57mA   -11.83mA
590.9mV   16.52mA    15.97mA    17.46mA
906.1mV   21.65mA    20.73mA    23.3mA
1.261V    23.76mA    22.65mA    25.8mA
1.733V    22.01mA    19.52mA    25.76mA
2.009V    18.19mA    8.04mA     21.29mA
2.364V    5.2mA      3mA        15.3mA
[Pullup]
-1.164V   7.3mA      4.009mA    11.8mA
-887.9mV  23.28mA    11.57mA    21.42mA
-730.3mV  24.71mA    20.07mA    22.27mA
-612.1mV  23.69mA    22.22mA    21.84mA
-375.8mV  17.4mA     16.45mA    16.97mA
215.2mV   -7.946mA   -7.529mA   -8.168mA
727.3mV   -18.74mA   -18.09mA   -19.68mA
1.515V    -22.28mA   -20.97mA   -24.1mA
1.791V    -20.54mA   -18.82mA   -23.03mA
1.988V    -19.79mA   -12.79mA   -21.91mA
2.224V    -12mA      -8.343mA   -21.22mA
2.382V    -8.7mA     -7.295mA   -14.29mA
[Ramp]
R_load=50.000Ohm
dV/dt_r   419.370mV/118.000ps  396.479mV/147.000ps  454.470mV/101.000ps
dV/dt_f   419.370mV/121.000ps  396.449mV/157.000ps  454.470mV/100.500ps
[Rising waveform]
R_fixture=50.000Ohm
V_fixture=1.200
V_fixture_min=1.140
V_fixture_max=1.300
0s        468.1mV    453.9mV    482.9mV
52ps      463.9mV    451.1mV    555.1mV
141ps     463.3mV    446mV      1.088V
179ps     505.2mV    446.1mV    1.178V
218ps     645.6mV    452.7mV    1.218V
269ps     916.2mV    484.1mV    1.239V
320ps     1.07V      586.7mV    1.247V
422ps     1.149V     948.3mV    1.252V
511ps     1.161V     1.073V     1.253V
1.25ns    1.166V     1.114V     1.253V
[Rising waveform]
R_fixture=50.000Ohm
V_fixture=0
0s        902.8uV    884.2uV    -6.476mV
64ps      -166.2uV   774uV      55.98mV
179ps     -1.324mV   -6.145mV   522.1mV
230ps     96.19mV    -11.52mV   634.6mV
294ps     320.6mV    4.828mV    702.6mV
409ps     592.2mV    222mV      741mV
524ps     673.2mV    492.4mV    749.7mV
613ps     691mV      594.3mV    752mV
792ps     699.7mV    652.2mV    753.4mV
1.25ns    701.9mV    664.2mV    753.6mV
[Falling waveform]
R_fixture=50.000Ohm
V_fixture=1.200
V_fixture_min=1.140
V_fixture_max=1.300
0s        1.165V     1.113V     1.258V
64ps      1.166V     1.113V     1.215V
192ps     1.151V     1.122V     701.8mV
243ps     1.036V     1.127V     592.6mV
307ps     819.6mV    1.096V     532.3mV
422ps     565.5mV    865.9mV    501.4mV
524ps     500.7mV    647.6mV    495.1mV
626ps     480.9mV    532.6mV    492.7mV
830ps     472.1mV    472.4mV    491.7mV
1.25ns    470mV      458.2mV    491.6mV
[Falling waveform]
R_fixture=50.000Ohm
V_fixture=0
0s        701.3mV    664.1mV    764.5mV
39ps      704mV      665.9mV    709.5mV
141ps     709.1mV    679.3mV    149mV
179ps     633.5mV    681.2mV    67.44mV
218ps     462.5mV    667.3mV    31.96mV
269ps     213.1mV    593.9mV    13.09mV
320ps     84.51mV    437.1mV    5.624mV
409ps     18.81mV    140.9mV    1.3mV
486ps     6.418mV    42.86mV    365.1uV
1.25ns    2.255uV    24.79uV    691.5nV
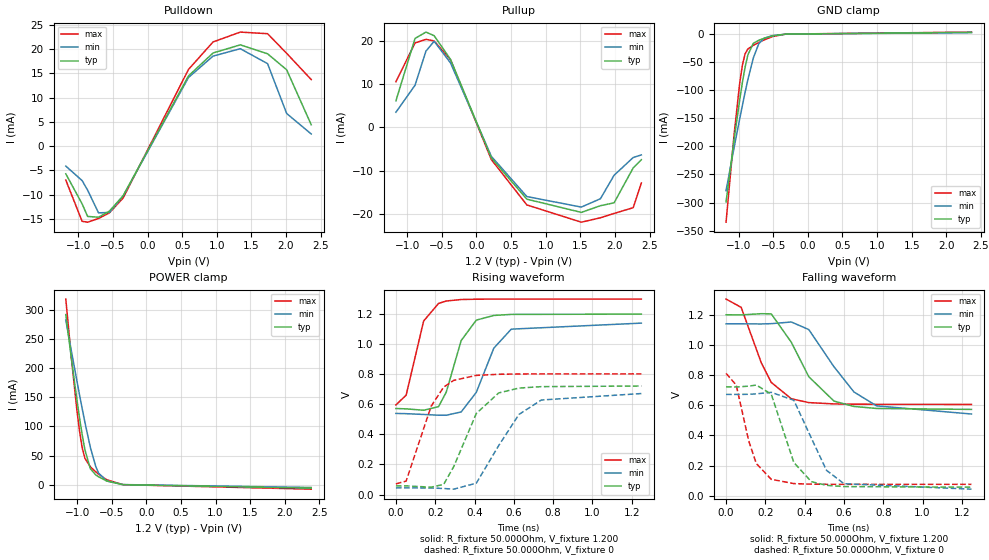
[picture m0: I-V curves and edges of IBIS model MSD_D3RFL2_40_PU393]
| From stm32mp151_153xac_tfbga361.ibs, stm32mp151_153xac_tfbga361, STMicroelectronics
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[Model] MSD_D3RFL2_40_PU393
Model_type   I/O
C_comp 2.377pF   2.291pF   2.503pF
Vinh = 820.000mV
Vinl = 380.000mV
Vmeas = 600.000mV
Vref = 600.000mV
[Model Spec]
Vinh   820.000mV   790.000mV   870.000mV
Vinl   380.000mV   350.000mV   430.000mV
Vmeas   600.000mV   570.000mV   650.000mV
Vref   600.000mV   570.000mV   650.000mV
[Temperature Range]   25.000   125.000   -40.000
[Voltage Range]   1.200V   1.140V   1.300V
[GND Clamp Reference]   0.00V   0.00V   0.00V
[Pulldown Reference]   0.00V   0.00V   0.00V
[POWER Clamp Reference]   1.200V   1.140V   1.300V
[Pullup Reference]   1.200V   1.140V   1.300V
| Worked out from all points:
|   slope of the pulldown table from 0 to 0.18 V, typ, clamps not added: 35.6 ohm
|   slope of the pullup table from 0 to 0.18 V, typ, clamps not added: 29.6 ohm
|   GND clamp passes 1 mA (typ) near -0.41 V on its own axis
|   POWER clamp passes 1 mA (typ) near -0.41 V on its own axis
|   rising waveform, R_fixture 50.000Ohm, V_fixture 1.200: 20-80 % time 90.2ps typ, 118ps min, 75.6ps max; typ from 0.572 V to 1.2 V
|   rising waveform, R_fixture 50.000Ohm, V_fixture 0: 20-80 % time 140ps typ, 175ps min, 117ps max; typ from 0.057 V to 0.722 V
|   falling waveform, R_fixture 50.000Ohm, V_fixture 1.200: 20-80 % time 163ps typ, 205ps min, 131ps max; typ from 1.2 V to 0.573 V
|   falling waveform, R_fixture 50.000Ohm, V_fixture 0: 20-80 % time 102ps typ, 127ps min, 85.1ps max; typ from 0.722 V to 0.057 V
[GND Clamp]
-1.182V   -298.8mA   -278.8mA   -334.9mA
-1.064V   -186.6mA   -201.1mA   -176.7mA
-984.9mV  -117.3mA   -151.1mA   -87.88mA
-945.5mV  -85.98mA   -126.9mA   -55.1mA
-906.1mV  -58.6mA    -103.4mA   -35.03mA
-866.7mV  -37.14mA   -81.28mA   -26.65mA
-787.9mV  -16.55mA   -42.62mA   -20.11mA
-709.1mV  -11.11mA   -17.23mA   -15.06mA
-630.3mV  -7.64mA    -7.317mA   -10.42mA
-512.1mV  -3.431mA   -2.91mA    -4.569mA
-315.1mV  -140uA     -201.2uA   -134.4uA
2.364V    2.893mA    2.444mA    3.402mA
[Power Clamp]
-1.164V   291.9mA    282.3mA    318.5mA
-1.085V   218.2mA    230.6mA    219.4mA
-1.006V   148mA      179.8mA    130.6mA
-966.7mV  115.5mA    154.9mA    92.81mA
-927.3mV  85.77mA    130.6mA    63.48mA
-887.9mV  60.06mA    107.1mA    45.4mA
-809.1mV  27.54mA    64.12mA    30.75mA
-730.3mV  16.82mA    31mA       22.11mA
-690.9mV  13.74mA    20.18mA    18.27mA
-572.7mV  6.53mA     6.478mA    8.613mA
-336.4mV  191.9uA    365.4uA    212.3uA
2.382V    -5.79mA    -4.601mA   -7.505mA
[Pulldown]
-1.182V   -5.7mA     -4.1mA     -7mA
-945.5mV  -11.9mA    -7.1mA     -15.47mA
-866.7mV  -14.47mA   -9.06mA    -15.65mA
-709.1mV  -14.62mA   -13.73mA   -14.89mA
-551.5mV  -13.37mA   -13.65mA   -13.72mA
-354.6mV  -10.22mA   -10.29mA   -10.7mA
590.9mV   14.46mA    14.13mA    15.79mA
945.5mV   19.17mA    18.53mA    21.44mA
1.339V    20.84mA    20.05mA    23.47mA
1.733V    19.01mA    16.98mA    23.14mA
2.009V    15.71mA    6.72mA     19.1mA
2.364V    4.4mA      2.5mA      13.7mA
[Pullup]
-1.164V   6.1mA      3.457mA    10.51mA
-887.9mV  20.5mA     9.7mA      19.46mA
-730.3mV  21.97mA    17.57mA    20.29mA
-612.1mV  21.14mA    19.85mA    19.93mA
-375.8mV  15.68mA    14.87mA    15.59mA
215.2mV   -7.105mA   -6.743mA   -7.481mA
727.3mV   -16.61mA   -16.01mA   -17.94mA
1.515V    -19.67mA   -18.44mA   -21.93mA
1.791V    -18.12mA   -16.51mA   -20.91mA
1.988V    -17.46mA   -11.09mA   -19.91mA
2.264V    -9.4mA     -6.995mA   -18.58mA
2.382V    -7.5mA     -6.395mA   -12.88mA
[Ramp]
R_load=50.000Ohm
dV/dt_r   387.774mV/115.500ps  368.652mV/147.000ps  426.210mV/96.500ps
dV/dt_f   387.774mV/133.500ps  368.562mV/167.500ps  426.210mV/108.500ps
[Rising waveform]
R_fixture=50.000Ohm
V_fixture=1.200
V_fixture_min=1.140
V_fixture_max=1.300
0s        572.2mV    539.5mV    596.4mV
52ps      570mV      537.9mV    660.8mV
141ps     560.7mV    532.7mV    1.154V
217ps     584.8mV    527.8mV    1.271V
256ps     680.8mV    527.5mV    1.287V
332ps     1.024V     549.4mV    1.297V
409ps     1.16V      679.7mV    1.299V
498ps     1.191V     973.2mV    1.3V
587ps     1.198V     1.1V       1.3V
1.249ns   1.2V       1.14V      1.3V
[Rising waveform]
R_fixture=50.000Ohm
V_fixture=0
0s        57.44mV    44.25mV    70.93mV
52ps      57.83mV    44.52mV    89.9mV
179ps     49.23mV    43.83mV    587mV
243ps     67.71mV    40.49mV    714.6mV
294ps     185.3mV    35.97mV    759.3mV
409ps     539mV      75.66mV    792.5mV
523ps     676mV      325.6mV    799.8mV
626ps     708.1mV    532.8mV    801.9mV
740ps     717.7mV    628.8mV    802.5mV
1.249ns   721.9mV    671.8mV    802.7mV
[Falling waveform]
R_fixture=50.000Ohm
V_fixture=1.200
V_fixture_min=1.140
V_fixture_max=1.300
0s        1.2V       1.14V      1.304V
77ps      1.199V     1.14V      1.249V
179ps     1.207V     1.139V     882.4mV
230ps     1.206V     1.141V     751.7mV
332ps     1.018V     1.152V     643.3mV
421ps     789.6mV    1.102V     617.9mV
549ps     628mV      855.8mV    609.1mV
651ps     592.3mV    688.2mV    607.3mV
766ps     579mV      596.2mV    606.6mV
1.249ns   572.7mV    542.2mV    605.8mV
[Falling waveform]
R_fixture=50.000Ohm
V_fixture=0
0s        721.6mV    672.2mV    811.8mV
52ps      721.4mV    671.9mV    733.7mV
115ps     726.9mV    672.9mV    366.3mV
154ps     734.2mV    675.8mV    214.1mV
230ps     674.1mV    685.9mV    109.4mV
345ps     220.8mV    633.2mV    81.16mV
434ps     93.85mV    382.7mV    77.37mV
511ps     69.67mV    169.2mV    76.56mV
600ps     61.32mV    80.36mV    76.33mV
1.249ns   57.23mV    44.16mV    76.21mV
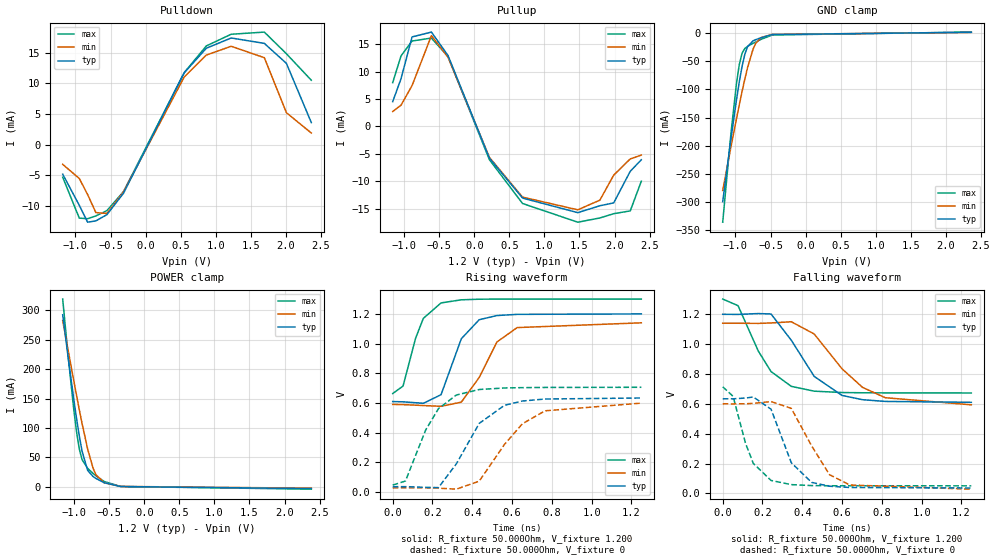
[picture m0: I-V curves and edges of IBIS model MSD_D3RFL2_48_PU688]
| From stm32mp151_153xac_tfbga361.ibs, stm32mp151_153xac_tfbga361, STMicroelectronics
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[Model] MSD_D3RFL2_48_PU688
Model_type   I/O
C_comp 2.464pF   2.377pF   2.591pF
Vinh = 820.000mV
Vinl = 380.000mV
Vmeas = 600.000mV
Vref = 600.000mV
[Model Spec]
Vinh   820.000mV   790.000mV   870.000mV
Vinl   380.000mV   350.000mV   430.000mV
Vmeas   600.000mV   570.000mV   650.000mV
Vref   600.000mV   570.000mV   650.000mV
[Temperature Range]   25.000   125.000   -40.000
[Voltage Range]   1.200V   1.140V   1.300V
[GND Clamp Reference]   0.00V   0.00V   0.00V
[Pulldown Reference]   0.00V   0.00V   0.00V
[POWER Clamp Reference]   1.200V   1.140V   1.300V
[Pullup Reference]   1.200V   1.140V   1.300V
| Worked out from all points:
|   slope of the pulldown table from 0 to 0.18 V, typ, clamps not added: 41.6 ohm
|   slope of the pullup table from 0 to 0.18 V, typ, clamps not added: 36.3 ohm
|   GND clamp passes 1 mA (typ) near -0.40 V on its own axis
|   POWER clamp passes 1 mA (typ) near -0.41 V on its own axis
|   rising waveform, R_fixture 50.000Ohm, V_fixture 1.200: 20-80 % time 99.5ps typ, 128ps min, 84.9ps max; typ from 0.61 V to 1.2 V
|   rising waveform, R_fixture 50.000Ohm, V_fixture 0: 20-80 % time 165ps typ, 199ps min, 140ps max; typ from 0.036 V to 0.634 V
|   falling waveform, R_fixture 50.000Ohm, V_fixture 1.200: 20-80 % time 180ps typ, 228ps min, 147ps max; typ from 1.2 V to 0.61 V
|   falling waveform, R_fixture 50.000Ohm, V_fixture 0: 20-80 % time 110ps typ, 136ps min, 93.7ps max; typ from 0.634 V to 0.036 V
[GND Clamp]
-1.182V   -299.5mA   -279.5mA   -335.8mA
-1.064V   -187.3mA   -201.8mA   -177.4mA
-984.9mV  -117.9mA   -151.6mA   -88.56mA
-945.5mV  -86.48mA   -127.3mA   -55.74mA
-906.1mV  -59.08mA   -103.8mA   -35.61mA
-866.7mV  -37.56mA   -81.65mA   -27.19mA
-827.3mV  -23.76mA   -61.08mA   -23.39mA
-748.5mV  -13.58mA   -28.09mA   -17.94mA
-709.1mV  -11.39mA   -17.47mA   -15.42mA
-630.3mV  -7.849mA   -7.504mA   -10.69mA
-472.7mV  -2.436mA   -2.132mA   -3.171mA
2.364V    1.653mA    1.397mA    1.945mA
[Power Clamp]
-1.164V   292.6mA    282.9mA    319.4mA
-1.085V   218.8mA    231.1mA    220.2mA
-1.006V   148.6mA    180.3mA    131.2mA
-966.7mV  116mA      155.4mA    93.45mA
-927.3mV  86.24mA    131mA      64.09mA
-887.9mV  60.5mA     107.5mA    45.96mA
-809.1mV  27.9mA     64.44mA    31.21mA
-730.3mV  17.1mA     31.25mA    22.47mA
-690.9mV  14mA       20.4mA     18.6mA
-572.7mV  6.682mA    6.615mA    8.806mA
-336.4mV  202.2uA    381.9uA    225.6uA
2.382V    -3.312mA   -2.631mA   -4.291mA
[Pulldown]
-1.182V   -4.8mA     -3.2mA     -5.3mA
-945.5mV  -9.87mA    -5.5mA     -11.96mA
-827.3mV  -12.62mA   -8.1mA     -12.05mA
-709.1mV  -12.41mA   -11.06mA   -11.6mA
-551.5mV  -11.39mA   -11.19mA   -10.73mA
-315.1mV  -7.911mA   -7.7mA     -7.644mA
551.5mV   11.72mA    11.04mA    11.75mA
866.7mV   15.71mA    14.6mA     16.09mA
1.221V    17.38mA    16.03mA    17.99mA
1.694V    16.5mA     14.17mA    18.34mA
2.009V    13.24mA    5.21mA     14.81mA
2.364V    3.6mA      1.9mA      10.5mA
[Pullup]
-1.164V   4.5mA      2.705mA    7.977mA
-1.045V   8.7mA      3.862mA    12.86mA
-887.9mV  16.31mA    7.437mA    15.56mA
-612.1mV  17.19mA    16.54mA    16.1mA
-375.8mV  12.93mA    12.63mA    12.73mA
215.2mV   -5.799mA   -5.652mA   -6.081mA
687.9mV   -13.08mA   -12.91mA   -14.07mA
1.476V    -15.74mA   -15.22mA   -17.48mA
1.791V    -14.48mA   -13.46mA   -16.71mA
1.988V    -13.96mA   -8.894mA   -15.93mA
2.224V    -8.2mA     -5.943mA   -15.42mA
2.382V    -6.1mA     -5.248mA   -10.01mA
[Ramp]
R_load=50.000Ohm
dV/dt_r   356.451mV/133.000ps  336.387mV/165.000ps  384.696mV/112.000ps
dV/dt_f   356.421mV/146.000ps  336.384mV/183.500ps  384.666mV/121.000ps
[Rising waveform]
R_fixture=50.000Ohm
V_fixture=1.200
V_fixture_min=1.140
V_fixture_max=1.300
0s        609.9mV    590.5mV    663.9mV
52ps      607.9mV    589mV      714.1mV
115ps     601.9mV    585.6mV    1.036V
154ps     597.9mV    582.8mV    1.17V
243ps     655.9mV    577.7mV    1.274V
345ps     1.033V     605.9mV    1.295V
435ps     1.161V     772.3mV    1.299V
524ps     1.189V     1.011V     1.3V
626ps     1.197V     1.108V     1.3V
1.25ns    1.2V       1.14V      1.3V
[Rising waveform]
R_fixture=50.000Ohm
V_fixture=0
0s        36.39mV    28.46mV    47.18mV
64ps      36.85mV    28.79mV    74.49mV
166ps     31.9mV     28.67mV    418.8mV
230ps     30.25mV    26.64mV    561.9mV
320ps     190.3mV    19.79mV    653.8mV
435ps     462.7mV    73.63mV    691mV
562ps     584.5mV    321.1mV    701.2mV
652ps     613.3mV    460.2mV    703.5mV
766ps     626.9mV    547.5mV    704.8mV
1.25ns    633.7mV    599.2mV    705.9mV
[Falling waveform]
R_fixture=50.000Ohm
V_fixture=1.200
V_fixture_min=1.140
V_fixture_max=1.300
0s        1.2V       1.14V      1.302V
77ps      1.199V     1.14V      1.258V
179ps     1.205V     1.139V     953.5mV
243ps     1.202V     1.142V     816.2mV
345ps     1.026V     1.15V      717.1mV
460ps     783.9mV    1.068V     685mV
600ps     656.3mV    834.7mV    675.8mV
703ps     627.8mV    710.4mV    674.2mV
817ps     616.2mV    641.1mV    673.5mV
1.25ns    610.2mV    593.5mV    672.9mV
[Falling waveform]
R_fixture=50.000Ohm
V_fixture=0
0s        633.9mV    600.1mV    714.4mV
52ps      633.6mV    599.8mV    650.6mV
115ps     638.9mV    600.6mV    334.5mV
154ps     646.1mV    603.4mV    200.9mV
243ps     564.1mV    615.3mV    86.86mV
345ps     205.2mV    569.7mV    58.8mV
447ps     73.89mV    318.5mV    52.56mV
537ps     48.02mV    125.4mV    51.35mV
639ps     39.74mV    56.41mV    50.98mV
1.25ns    36.24mV    28.42mV    50.78mV
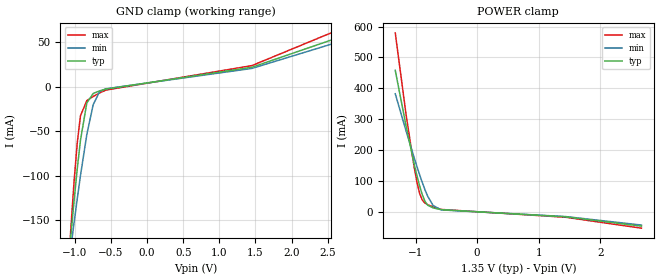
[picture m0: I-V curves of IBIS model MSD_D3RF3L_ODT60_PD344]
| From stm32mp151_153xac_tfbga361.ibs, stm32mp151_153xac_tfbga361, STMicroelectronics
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[Model] MSD_D3RF3L_ODT60_PD344
Model_type   Input
C_comp 2.287pF   2.238pF   2.354pF
Vinh = 810.000mV
Vinl = 540.000mV
[Temperature Range]   25.000   125.000   -40.000
[Voltage Range]   1.350V   1.283V   1.450V
[GND Clamp Reference]   0.00V   0.00V   0.00V
[POWER Clamp Reference]   1.350V   1.283V   1.450V
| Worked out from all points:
|   GND clamp passes 1 mA (typ) near -0.46 V on its own axis
|   POWER clamp passes 1 mA (typ) near -0.18 V on its own axis
[GND Clamp]
-1.318V   -428.9mA   -356mA     -544.1mA
-1.098V   -208.4mA   -209.1mA   -216mA
-1.055V   -167mA     -180.7mA   -158.1mA
-1.011V   -127.9mA   -152.8mA   -106.2mA
-966.7mV  -91.79mA   -125.8mA   -62.72mA
-922.7mV  -60.24mA   -99.96mA   -32.75mA
-834.9mV  -18.29mA   -53.8mA    -15.62mA
-747mV    -7.683mA   -20.34mA   -11.01mA
-659.1mV  -4.764mA   -5.679mA   -7.09mA
-571.2mV  -2.675mA   -2.328mA   -3.822mA
1.45V     21.82mA    20.52mA    23.68mA
2.68V     56.09mA    51.04mA    64.95mA
[Power Clamp]
-1.33V    458mA      382.1mA    579.3mA
-1.155V   278.6mA    262.2mA    315.5mA
-1.023V   154.1mA    175.1mA    144.6mA
-978.8mV  117.3mA    147.2mA    97.11mA
-934.9mV  84.02mA    120.1mA    59.78mA
-890.9mV  55.31mA    94.58mA    37.81mA
-847mV    33.62mA    71.03mA    28.02mA
-803mV    21.15mA    50.19mA    22.96mA
-715.1mV  12.51mA    20.3mA     15.59mA
-583.3mV  6.723mA    5.99mA     7.427mA
1.438V    -16.4mA    -15.62mA   -17.88mA
2.668V    -46.65mA   -43.04mA   -53.13mA
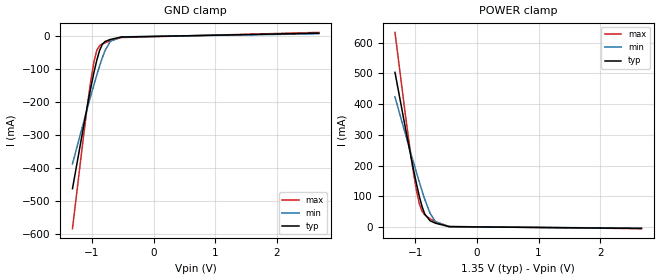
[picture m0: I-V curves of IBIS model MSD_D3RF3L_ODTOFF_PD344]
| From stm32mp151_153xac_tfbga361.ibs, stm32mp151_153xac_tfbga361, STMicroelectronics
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[Model] MSD_D3RF3L_ODTOFF_PD344
Model_type   Input
C_comp 2.333pF   2.249pF   2.455pF
Vinh = 810.000mV
Vinl = 540.000mV
[Temperature Range]   25.000   125.000   -40.000
[Voltage Range]   1.350V   1.283V   1.450V
[GND Clamp Reference]   0.00V   0.00V   0.00V
[POWER Clamp Reference]   1.350V   1.283V   1.450V
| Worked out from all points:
|   GND clamp passes 1 mA (typ) near -0.40 V on its own axis
|   POWER clamp passes 1 mA (typ) near -0.41 V on its own axis
[GND Clamp]
-1.318V   -463.1mA   -387.8mA   -584mA
-1.142V   -278.9mA   -264.8mA   -309mA
-1.055V   -190.5mA   -204.6mA   -181mA
-1.011V   -148.3mA   -175.1mA   -123.8mA
-966.7mV  -108.8mA   -146.3mA   -76.3mA
-922.7mV  -73.48mA   -118.4mA   -44.15mA
-878.8mV  -45mA      -91.85mA   -29.99mA
-834.9mV  -26.41mA   -67.25mA   -24.79mA
-790.9mV  -17.55mA   -45.61mA   -21.41mA
-703mV    -11.2mA    -16.48mA   -15.41mA
-527.3mV  -3.993mA   -3.363mA   -5.386mA
2.68V     7.796mA    6.062mA    10.12mA
[Power Clamp]
-1.33V    503.2mA    423.2mA    633mA
-1.155V   316.2mA    298.3mA    355.9mA
-1.067V   225mA      236.6mA    226.2mA
-1.023V   180.9mA    206.1mA    167.9mA
-978.8mV  138.8mA    176.1mA    116.5mA
-934.9mV  100.2mA    146.6mA    76.3mA
-890.9mV  67.25mA    118mA      51.95mA
-847mV    42.54mA    90.92mA    40.07mA
-759.1mV  20.81mA    44.69mA    27.43mA
-671.2mV  12.98mA    17.26mA    17.7mA
-451.5mV  1.813mA    2.044mA    2.306mA
2.668V    -3.92mA    -3.261mA   -4.67mA
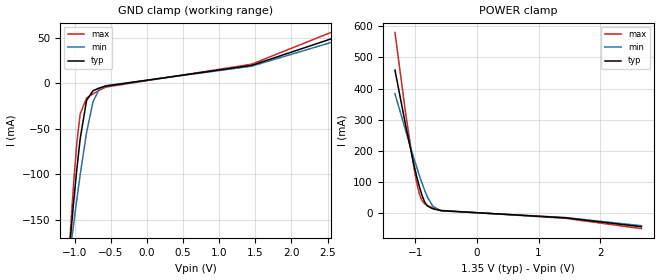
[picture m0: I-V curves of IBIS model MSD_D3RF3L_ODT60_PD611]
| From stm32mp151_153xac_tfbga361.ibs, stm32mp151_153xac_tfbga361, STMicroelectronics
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[Model] MSD_D3RF3L_ODT60_PD611
Model_type   Input
C_comp 2.393pF   2.343pF   2.462pF
Vinh = 810.000mV
Vinl = 540.000mV
[Temperature Range]   25.000   125.000   -40.000
[Voltage Range]   1.350V   1.283V   1.450V
[GND Clamp Reference]   0.00V   0.00V   0.00V
[POWER Clamp Reference]   1.350V   1.283V   1.450V
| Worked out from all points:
|   GND clamp passes 1 mA (typ) near -0.45 V on its own axis
|   POWER clamp passes 1 mA (typ) near -0.18 V on its own axis
[GND Clamp]
-1.318V   -430mA     -356.9mA   -545.3mA
-1.098V   -209.2mA   -209.7mA   -216.9mA
-1.055V   -167.7mA   -181.2mA   -158.9mA
-1.011V   -128.5mA   -153.3mA   -106.9mA
-966.7mV  -92.45mA   -126.3mA   -63.5mA
-922.7mV  -60.77mA   -100.4mA   -33.42mA
-834.9mV  -18.73mA   -54.15mA   -16.16mA
-747mV    -8.026mA   -20.62mA   -11.43mA
-659.1mV  -5.022mA   -5.89mA    -7.41mA
-571.2mV  -2.849mA   -2.478mA   -4.028mA
1.45V     19.96mA    19.07mA    21.27mA
2.68V     52.67mA    48.37mA    60.53mA
[Power Clamp]
-1.33V    459.1mA    383.1mA    580.7mA
-1.155V   279.5mA    263.1mA    316.6mA
-1.023V   154.8mA    175.8mA    145.5mA
-978.8mV  118mA      147.7mA    97.92mA
-934.9mV  84.64mA    120.7mA    60.52mA
-890.9mV  55.88mA    95.1mA     38.5mA
-847mV    34.14mA    71.48mA    28.65mA
-803mV    21.61mA    50.61mA    23.52mA
-715.1mV  12.86mA    20.63mA    16.01mA
-583.3mV  6.938mA    6.198mA    7.68mA
1.438V    -16.29mA   -15.46mA   -17.88mA
2.668V    -44.94mA   -41.61mA   -51.13mA
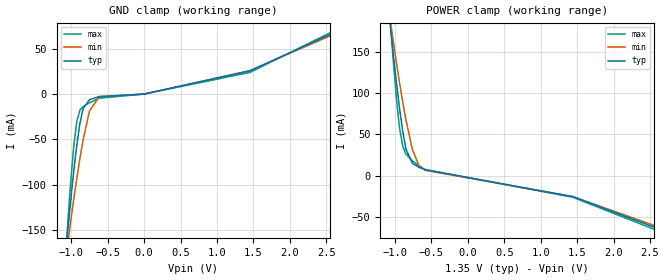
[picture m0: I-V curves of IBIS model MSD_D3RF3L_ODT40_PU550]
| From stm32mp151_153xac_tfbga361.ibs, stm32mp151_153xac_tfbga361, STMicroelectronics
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[Model] MSD_D3RF3L_ODT40_PU550
Model_type   Input
C_comp 2.363pF   2.322pF   2.416pF
Vinh = 810.000mV
Vinl = 540.000mV
[Temperature Range]   25.000   125.000   -40.000
[Voltage Range]   1.350V   1.283V   1.450V
[GND Clamp Reference]   0.00V   0.00V   0.00V
[POWER Clamp Reference]   1.350V   1.283V   1.450V
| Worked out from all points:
|   GND clamp passes 1 mA (typ) near -0.47 V on its own axis
|   POWER clamp passes 1 mA (typ) near -0.15 V on its own axis
[GND Clamp]
-1.318V   -415.5mA   -341.5mA   -533.7mA
-1.055V   -159.4mA   -170.6mA   -153.5mA
-1.011V   -121.8mA   -143.8mA   -102.9mA
-966.7mV  -87.26mA   -118mA     -60.02mA
-922.7mV  -56.81mA   -93.52mA   -30.39mA
-878.8mV  -32.16mA   -70.8mA    -17.72mA
-834.9mV  -16.02mA   -50.2mA    -13.75mA
-747mV    -6.066mA   -18.58mA   -9.578mA
-615.1mV  -2.862mA   -2.858mA   -4.566mA
200nV     3.383nA    3.269nA    3.448nA
1.45V     25.55mA    25.93mA    23.83mA
2.68V     70.52mA    68.77mA    72.83mA
[Power Clamp]
-1.33V    441.3mA    364mA      566.4mA
-1.067V   185.2mA    190.6mA    192.7mA
-1.023V   148mA      163.4mA    140.5mA
-978.8mV  113mA      137mA      93.7mA
-934.9mV  80.94mA    112mA      56.9mA
-890.9mV  53.04mA    88.56mA    35.43mA
-847mV    31.94mA    66.99mA    26.1mA
-759.1mV  14.76mA    31.74mA    17.89mA
-671.2mV  10.2mA     12.35mA    11.97mA
-583.3mV  7.245mA    6.525mA    7.478mA
1.438V    -25.3mA    -25.1mA    -25.96mA
2.668V    -65.96mA   -63.68mA   -68.77mA
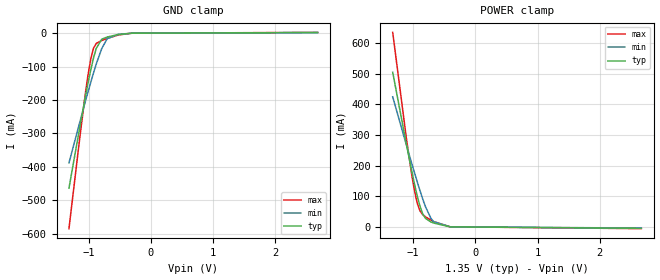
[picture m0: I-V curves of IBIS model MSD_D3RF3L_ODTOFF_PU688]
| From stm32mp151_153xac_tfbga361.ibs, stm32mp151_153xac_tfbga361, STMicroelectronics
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[Model] MSD_D3RF3L_ODTOFF_PU688
Model_type   Input
C_comp 2.455pF   2.369pF   2.579pF
Vinh = 810.000mV
Vinl = 540.000mV
[Temperature Range]   25.000   125.000   -40.000
[Voltage Range]   1.350V   1.283V   1.450V
[GND Clamp Reference]   0.00V   0.00V   0.00V
[POWER Clamp Reference]   1.350V   1.283V   1.450V
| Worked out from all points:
|   GND clamp passes 1 mA (typ) near -0.40 V on its own axis
|   POWER clamp passes 1 mA (typ) near -0.41 V on its own axis
[GND Clamp]
-1.318V   -464.2mA   -388.6mA   -585.4mA
-1.142V   -279.7mA   -265.4mA   -310.1mA
-1.055V   -191.2mA   -205.1mA   -181.9mA
-1.011V   -149mA     -175.7mA   -124.8mA
-966.7mV  -109.4mA   -146.8mA   -77.16mA
-922.7mV  -74.06mA   -118.9mA   -44.93mA
-878.8mV  -45.53mA   -92.26mA   -30.7mA
-790.9mV  -17.98mA   -45.94mA   -21.98mA
-703mV    -11.54mA   -16.73mA   -15.85mA
-527.3mV  -4.141mA   -3.476mA   -5.586mA
-307.6mV  -130.2uA   -188uA     -117.4uA
2.68V     1.938mA    1.644mA    2.298mA
[Power Clamp]
-1.33V    504.7mA    424.5mA    634.6mA
-1.111V   271.3mA    268.3mA    290.7mA
-1.023V   181.7mA    206.9mA    168.9mA
-978.8mV  139.7mA    176.9mA    117.6mA
-934.9mV  101mA      147.3mA    77.22mA
-890.9mV  67.93mA    118.7mA    52.77mA
-847mV    43.16mA    91.53mA    40.81mA
-803mV    28.55mA    66.6mA     33.76mA
-715.1mV  16.87mA    28.61mA    22.85mA
-671.2mV  13.34mA    17.63mA    18.15mA
-407.6mV  950.3uA    1.241mA    1.157mA
2.668V    -3.817mA   -3.061mA   -4.926mA
